VERSION 5.8 ;
BUSBITCHARS "[]" ;
DIVIDERCHAR "/" ;
UNITS
    DATABASE MICRONS 1000 ;
END UNITS

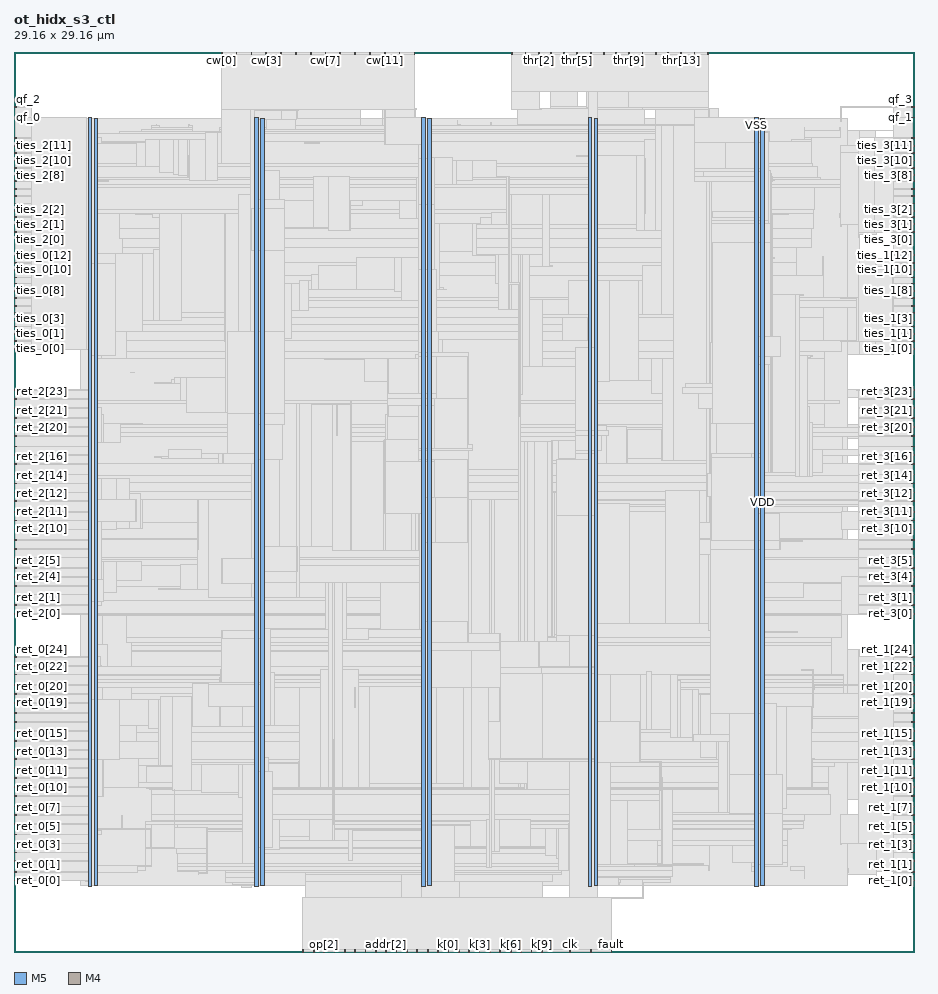
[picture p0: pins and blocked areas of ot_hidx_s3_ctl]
MACRO ot_hidx_s3_ctl
  FOREIGN ot_hidx_s3_ctl 0 0 ;
  CLASS BLOCK ;
  SIZE 29.16 BY 29.16 ;
  PIN addr[0]
    DIRECTION INPUT ;
    USE SIGNAL ;
    PORT
      LAYER M5 ;
        RECT  11.376 0 11.4 0.084 ;
    END
  END addr[0]
  PIN addr[1]
    DIRECTION INPUT ;
    USE SIGNAL ;
    PORT
      LAYER M5 ;
        RECT  11.712 0 11.736 0.084 ;
    END
  END addr[1]
  PIN addr[2]
    DIRECTION INPUT ;
    USE SIGNAL ;
    PORT
      LAYER M5 ;
        RECT  12.048 0 12.072 0.084 ;
    END
  END addr[2]
  PIN addr[3]
    DIRECTION INPUT ;
    USE SIGNAL ;
    PORT
      LAYER M5 ;
        RECT  12.384 0 12.408 0.084 ;
    END
  END addr[3]
  PIN addr[4]
    DIRECTION INPUT ;
    USE SIGNAL ;
    PORT
      LAYER M5 ;
        RECT  12.72 0 12.744 0.084 ;
    END
  END addr[4]
  PIN addr[5]
    DIRECTION INPUT ;
    USE SIGNAL ;
    PORT
      LAYER M5 ;
        RECT  13.056 0 13.08 0.084 ;
    END
  END addr[5]
  PIN addr[6]
    DIRECTION INPUT ;
    USE SIGNAL ;
    PORT
      LAYER M5 ;
        RECT  13.392 0 13.416 0.084 ;
    END
  END addr[6]
  PIN addr[7]
    DIRECTION INPUT ;
    USE SIGNAL ;
    PORT
      LAYER M5 ;
        RECT  13.728 0 13.752 0.084 ;
    END
  END addr[7]
  PIN clk
    DIRECTION INPUT ;
    USE SIGNAL ;
    PORT
      LAYER M5 ;
        RECT  18 0 18.024 0.084 ;
    END
  END clk
  PIN cw[0]
    DIRECTION OUTPUT ;
    USE SIGNAL ;
    PORT
      LAYER M5 ;
        RECT  6.72 29.076 6.744 29.16 ;
    END
  END cw[0]
  PIN cw[10]
    DIRECTION OUTPUT ;
    USE SIGNAL ;
    PORT
      LAYER M5 ;
        RECT  11.52 29.076 11.544 29.16 ;
    END
  END cw[10]
  PIN cw[11]
    DIRECTION OUTPUT ;
    USE SIGNAL ;
    PORT
      LAYER M5 ;
        RECT  12 29.076 12.024 29.16 ;
    END
  END cw[11]
  PIN cw[12]
    DIRECTION OUTPUT ;
    USE SIGNAL ;
    PORT
      LAYER M5 ;
        RECT  12.48 29.076 12.504 29.16 ;
    END
  END cw[12]
  PIN cw[13]
    DIRECTION OUTPUT ;
    USE SIGNAL ;
    PORT
      LAYER M5 ;
        RECT  12.96 29.076 12.984 29.16 ;
    END
  END cw[13]
  PIN cw[1]
    DIRECTION OUTPUT ;
    USE SIGNAL ;
    PORT
      LAYER M5 ;
        RECT  7.2 29.076 7.224 29.16 ;
    END
  END cw[1]
  PIN cw[2]
    DIRECTION OUTPUT ;
    USE SIGNAL ;
    PORT
      LAYER M5 ;
        RECT  7.68 29.076 7.704 29.16 ;
    END
  END cw[2]
  PIN cw[3]
    DIRECTION OUTPUT ;
    USE SIGNAL ;
    PORT
      LAYER M5 ;
        RECT  8.16 29.076 8.184 29.16 ;
    END
  END cw[3]
  PIN cw[4]
    DIRECTION OUTPUT ;
    USE SIGNAL ;
    PORT
      LAYER M5 ;
        RECT  8.64 29.076 8.664 29.16 ;
    END
  END cw[4]
  PIN cw[5]
    DIRECTION OUTPUT ;
    USE SIGNAL ;
    PORT
      LAYER M5 ;
        RECT  9.12 29.076 9.144 29.16 ;
    END
  END cw[5]
  PIN cw[6]
    DIRECTION OUTPUT ;
    USE SIGNAL ;
    PORT
      LAYER M5 ;
        RECT  9.6 29.076 9.624 29.16 ;
    END
  END cw[6]
  PIN cw[7]
    DIRECTION OUTPUT ;
    USE SIGNAL ;
    PORT
      LAYER M5 ;
        RECT  10.08 29.076 10.104 29.16 ;
    END
  END cw[7]
  PIN cw[8]
    DIRECTION OUTPUT ;
    USE SIGNAL ;
    PORT
      LAYER M5 ;
        RECT  10.56 29.076 10.584 29.16 ;
    END
  END cw[8]
  PIN cw[9]
    DIRECTION OUTPUT ;
    USE SIGNAL ;
    PORT
      LAYER M5 ;
        RECT  11.04 29.076 11.064 29.16 ;
    END
  END cw[9]
  PIN fault
    DIRECTION OUTPUT ;
    USE SIGNAL ;
    PORT
      LAYER M5 ;
        RECT  19.344 0 19.368 0.084 ;
    END
  END fault
  PIN k[0]
    DIRECTION INPUT ;
    USE SIGNAL ;
    PORT
      LAYER M5 ;
        RECT  14.064 0 14.088 0.084 ;
    END
  END k[0]
  PIN k[1]
    DIRECTION INPUT ;
    USE SIGNAL ;
    PORT
      LAYER M5 ;
        RECT  14.4 0 14.424 0.084 ;
    END
  END k[1]
  PIN k[2]
    DIRECTION INPUT ;
    USE SIGNAL ;
    PORT
      LAYER M5 ;
        RECT  14.736 0 14.76 0.084 ;
    END
  END k[2]
  PIN k[3]
    DIRECTION INPUT ;
    USE SIGNAL ;
    PORT
      LAYER M5 ;
        RECT  15.072 0 15.096 0.084 ;
    END
  END k[3]
  PIN k[4]
    DIRECTION INPUT ;
    USE SIGNAL ;
    PORT
      LAYER M5 ;
        RECT  15.408 0 15.432 0.084 ;
    END
  END k[4]
  PIN k[5]
    DIRECTION INPUT ;
    USE SIGNAL ;
    PORT
      LAYER M5 ;
        RECT  15.744 0 15.768 0.084 ;
    END
  END k[5]
  PIN k[6]
    DIRECTION INPUT ;
    USE SIGNAL ;
    PORT
      LAYER M5 ;
        RECT  16.08 0 16.104 0.084 ;
    END
  END k[6]
  PIN k[7]
    DIRECTION INPUT ;
    USE SIGNAL ;
    PORT
      LAYER M5 ;
        RECT  16.416 0 16.44 0.084 ;
    END
  END k[7]
  PIN k[8]
    DIRECTION INPUT ;
    USE SIGNAL ;
    PORT
      LAYER M5 ;
        RECT  16.752 0 16.776 0.084 ;
    END
  END k[8]
  PIN k[9]
    DIRECTION INPUT ;
    USE SIGNAL ;
    PORT
      LAYER M5 ;
        RECT  17.088 0 17.112 0.084 ;
    END
  END k[9]
  PIN op[0]
    DIRECTION INPUT ;
    USE SIGNAL ;
    PORT
      LAYER M5 ;
        RECT  9.36 0 9.384 0.084 ;
    END
  END op[0]
  PIN op[1]
    DIRECTION INPUT ;
    USE SIGNAL ;
    PORT
      LAYER M5 ;
        RECT  9.696 0 9.72 0.084 ;
    END
  END op[1]
  PIN op[2]
    DIRECTION INPUT ;
    USE SIGNAL ;
    PORT
      LAYER M5 ;
        RECT  10.032 0 10.056 0.084 ;
    END
  END op[2]
  PIN op[3]
    DIRECTION INPUT ;
    USE SIGNAL ;
    PORT
      LAYER M5 ;
        RECT  10.368 0 10.392 0.084 ;
    END
  END op[3]
  PIN pass[0]
    DIRECTION INPUT ;
    USE SIGNAL ;
    PORT
      LAYER M5 ;
        RECT  10.704 0 10.728 0.084 ;
    END
  END pass[0]
  PIN pass[1]
    DIRECTION INPUT ;
    USE SIGNAL ;
    PORT
      LAYER M5 ;
        RECT  11.04 0 11.064 0.084 ;
    END
  END pass[1]
  PIN qf_0
    DIRECTION INPUT ;
    USE SIGNAL ;
    PORT
      LAYER M4 ;
        RECT  0 27.024 0.084 27.048 ;
    END
  END qf_0
  PIN qf_1
    DIRECTION INPUT ;
    USE SIGNAL ;
    PORT
      LAYER M4 ;
        RECT  29.076 27.024 29.16 27.048 ;
    END
  END qf_1
  PIN qf_2
    DIRECTION INPUT ;
    USE SIGNAL ;
    PORT
      LAYER M4 ;
        RECT  0 27.36 0.084 27.384 ;
    END
  END qf_2
  PIN qf_3
    DIRECTION INPUT ;
    USE SIGNAL ;
    PORT
      LAYER M4 ;
        RECT  29.076 27.36 29.16 27.384 ;
    END
  END qf_3
  PIN ret_0[0]
    DIRECTION INPUT ;
    USE SIGNAL ;
    PORT
      LAYER M4 ;
        RECT  0 2.304 0.084 2.328 ;
    END
  END ret_0[0]
  PIN ret_0[10]
    DIRECTION INPUT ;
    USE SIGNAL ;
    PORT
      LAYER M4 ;
        RECT  0 5.328 0.084 5.352 ;
    END
  END ret_0[10]
  PIN ret_0[11]
    DIRECTION INPUT ;
    USE SIGNAL ;
    PORT
      LAYER M4 ;
        RECT  0 5.616 0.084 5.64 ;
    END
  END ret_0[11]
  PIN ret_0[12]
    DIRECTION INPUT ;
    USE SIGNAL ;
    PORT
      LAYER M4 ;
        RECT  0 5.952 0.084 5.976 ;
    END
  END ret_0[12]
  PIN ret_0[13]
    DIRECTION INPUT ;
    USE SIGNAL ;
    PORT
      LAYER M4 ;
        RECT  0 6.24 0.084 6.264 ;
    END
  END ret_0[13]
  PIN ret_0[14]
    DIRECTION INPUT ;
    USE SIGNAL ;
    PORT
      LAYER M4 ;
        RECT  0 6.528 0.084 6.552 ;
    END
  END ret_0[14]
  PIN ret_0[15]
    DIRECTION INPUT ;
    USE SIGNAL ;
    PORT
      LAYER M4 ;
        RECT  0 6.816 0.084 6.84 ;
    END
  END ret_0[15]
  PIN ret_0[16]
    DIRECTION INPUT ;
    USE SIGNAL ;
    PORT
      LAYER M4 ;
        RECT  0 7.152 0.084 7.176 ;
    END
  END ret_0[16]
  PIN ret_0[17]
    DIRECTION INPUT ;
    USE SIGNAL ;
    PORT
      LAYER M4 ;
        RECT  0 7.44 0.084 7.464 ;
    END
  END ret_0[17]
  PIN ret_0[18]
    DIRECTION INPUT ;
    USE SIGNAL ;
    PORT
      LAYER M4 ;
        RECT  0 7.728 0.084 7.752 ;
    END
  END ret_0[18]
  PIN ret_0[19]
    DIRECTION INPUT ;
    USE SIGNAL ;
    PORT
      LAYER M4 ;
        RECT  0 8.064 0.084 8.088 ;
    END
  END ret_0[19]
  PIN ret_0[1]
    DIRECTION INPUT ;
    USE SIGNAL ;
    PORT
      LAYER M4 ;
        RECT  0 2.592 0.084 2.616 ;
    END
  END ret_0[1]
  PIN ret_0[20]
    DIRECTION INPUT ;
    USE SIGNAL ;
    PORT
      LAYER M4 ;
        RECT  0 8.352 0.084 8.376 ;
    END
  END ret_0[20]
  PIN ret_0[21]
    DIRECTION INPUT ;
    USE SIGNAL ;
    PORT
      LAYER M4 ;
        RECT  0 8.64 0.084 8.664 ;
    END
  END ret_0[21]
  PIN ret_0[22]
    DIRECTION INPUT ;
    USE SIGNAL ;
    PORT
      LAYER M4 ;
        RECT  0 8.976 0.084 9 ;
    END
  END ret_0[22]
  PIN ret_0[23]
    DIRECTION INPUT ;
    USE SIGNAL ;
    PORT
      LAYER M4 ;
        RECT  0 9.264 0.084 9.288 ;
    END
  END ret_0[23]
  PIN ret_0[24]
    DIRECTION INPUT ;
    USE SIGNAL ;
    PORT
      LAYER M4 ;
        RECT  0 9.552 0.084 9.576 ;
    END
  END ret_0[24]
  PIN ret_0[2]
    DIRECTION INPUT ;
    USE SIGNAL ;
    PORT
      LAYER M4 ;
        RECT  0 2.928 0.084 2.952 ;
    END
  END ret_0[2]
  PIN ret_0[3]
    DIRECTION INPUT ;
    USE SIGNAL ;
    PORT
      LAYER M4 ;
        RECT  0 3.216 0.084 3.24 ;
    END
  END ret_0[3]
  PIN ret_0[4]
    DIRECTION INPUT ;
    USE SIGNAL ;
    PORT
      LAYER M4 ;
        RECT  0 3.504 0.084 3.528 ;
    END
  END ret_0[4]
  PIN ret_0[5]
    DIRECTION INPUT ;
    USE SIGNAL ;
    PORT
      LAYER M4 ;
        RECT  0 3.792 0.084 3.816 ;
    END
  END ret_0[5]
  PIN ret_0[6]
    DIRECTION INPUT ;
    USE SIGNAL ;
    PORT
      LAYER M4 ;
        RECT  0 4.128 0.084 4.152 ;
    END
  END ret_0[6]
  PIN ret_0[7]
    DIRECTION INPUT ;
    USE SIGNAL ;
    PORT
      LAYER M4 ;
        RECT  0 4.416 0.084 4.44 ;
    END
  END ret_0[7]
  PIN ret_0[8]
    DIRECTION INPUT ;
    USE SIGNAL ;
    PORT
      LAYER M4 ;
        RECT  0 4.704 0.084 4.728 ;
    END
  END ret_0[8]
  PIN ret_0[9]
    DIRECTION INPUT ;
    USE SIGNAL ;
    PORT
      LAYER M4 ;
        RECT  0 5.04 0.084 5.064 ;
    END
  END ret_0[9]
  PIN ret_1[0]
    DIRECTION INPUT ;
    USE SIGNAL ;
    PORT
      LAYER M4 ;
        RECT  29.076 2.304 29.16 2.328 ;
    END
  END ret_1[0]
  PIN ret_1[10]
    DIRECTION INPUT ;
    USE SIGNAL ;
    PORT
      LAYER M4 ;
        RECT  29.076 5.328 29.16 5.352 ;
    END
  END ret_1[10]
  PIN ret_1[11]
    DIRECTION INPUT ;
    USE SIGNAL ;
    PORT
      LAYER M4 ;
        RECT  29.076 5.616 29.16 5.64 ;
    END
  END ret_1[11]
  PIN ret_1[12]
    DIRECTION INPUT ;
    USE SIGNAL ;
    PORT
      LAYER M4 ;
        RECT  29.076 5.952 29.16 5.976 ;
    END
  END ret_1[12]
  PIN ret_1[13]
    DIRECTION INPUT ;
    USE SIGNAL ;
    PORT
      LAYER M4 ;
        RECT  29.076 6.24 29.16 6.264 ;
    END
  END ret_1[13]
  PIN ret_1[14]
    DIRECTION INPUT ;
    USE SIGNAL ;
    PORT
      LAYER M4 ;
        RECT  29.076 6.528 29.16 6.552 ;
    END
  END ret_1[14]
  PIN ret_1[15]
    DIRECTION INPUT ;
    USE SIGNAL ;
    PORT
      LAYER M4 ;
        RECT  29.076 6.816 29.16 6.84 ;
    END
  END ret_1[15]
  PIN ret_1[16]
    DIRECTION INPUT ;
    USE SIGNAL ;
    PORT
      LAYER M4 ;
        RECT  29.076 7.152 29.16 7.176 ;
    END
  END ret_1[16]
  PIN ret_1[17]
    DIRECTION INPUT ;
    USE SIGNAL ;
    PORT
      LAYER M4 ;
        RECT  29.076 7.44 29.16 7.464 ;
    END
  END ret_1[17]
  PIN ret_1[18]
    DIRECTION INPUT ;
    USE SIGNAL ;
    PORT
      LAYER M4 ;
        RECT  29.076 7.728 29.16 7.752 ;
    END
  END ret_1[18]
  PIN ret_1[19]
    DIRECTION INPUT ;
    USE SIGNAL ;
    PORT
      LAYER M4 ;
        RECT  29.076 8.064 29.16 8.088 ;
    END
  END ret_1[19]
  PIN ret_1[1]
    DIRECTION INPUT ;
    USE SIGNAL ;
    PORT
      LAYER M4 ;
        RECT  29.076 2.592 29.16 2.616 ;
    END
  END ret_1[1]
  PIN ret_1[20]
    DIRECTION INPUT ;
    USE SIGNAL ;
    PORT
      LAYER M4 ;
        RECT  29.076 8.352 29.16 8.376 ;
    END
  END ret_1[20]
  PIN ret_1[21]
    DIRECTION INPUT ;
    USE SIGNAL ;
    PORT
      LAYER M4 ;
        RECT  29.076 8.64 29.16 8.664 ;
    END
  END ret_1[21]
  PIN ret_1[22]
    DIRECTION INPUT ;
    USE SIGNAL ;
    PORT
      LAYER M4 ;
        RECT  29.076 8.976 29.16 9 ;
    END
  END ret_1[22]
  PIN ret_1[23]
    DIRECTION INPUT ;
    USE SIGNAL ;
    PORT
      LAYER M4 ;
        RECT  29.076 9.264 29.16 9.288 ;
    END
  END ret_1[23]
  PIN ret_1[24]
    DIRECTION INPUT ;
    USE SIGNAL ;
    PORT
      LAYER M4 ;
        RECT  29.076 9.552 29.16 9.576 ;
    END
  END ret_1[24]
  PIN ret_1[2]
    DIRECTION INPUT ;
    USE SIGNAL ;
    PORT
      LAYER M4 ;
        RECT  29.076 2.928 29.16 2.952 ;
    END
  END ret_1[2]
  PIN ret_1[3]
    DIRECTION INPUT ;
    USE SIGNAL ;
    PORT
      LAYER M4 ;
        RECT  29.076 3.216 29.16 3.24 ;
    END
  END ret_1[3]
  PIN ret_1[4]
    DIRECTION INPUT ;
    USE SIGNAL ;
    PORT
      LAYER M4 ;
        RECT  29.076 3.504 29.16 3.528 ;
    END
  END ret_1[4]
  PIN ret_1[5]
    DIRECTION INPUT ;
    USE SIGNAL ;
    PORT
      LAYER M4 ;
        RECT  29.076 3.792 29.16 3.816 ;
    END
  END ret_1[5]
  PIN ret_1[6]
    DIRECTION INPUT ;
    USE SIGNAL ;
    PORT
      LAYER M4 ;
        RECT  29.076 4.128 29.16 4.152 ;
    END
  END ret_1[6]
  PIN ret_1[7]
    DIRECTION INPUT ;
    USE SIGNAL ;
    PORT
      LAYER M4 ;
        RECT  29.076 4.416 29.16 4.44 ;
    END
  END ret_1[7]
  PIN ret_1[8]
    DIRECTION INPUT ;
    USE SIGNAL ;
    PORT
      LAYER M4 ;
        RECT  29.076 4.704 29.16 4.728 ;
    END
  END ret_1[8]
  PIN ret_1[9]
    DIRECTION INPUT ;
    USE SIGNAL ;
    PORT
      LAYER M4 ;
        RECT  29.076 5.04 29.16 5.064 ;
    END
  END ret_1[9]
  PIN ret_2[0]
    DIRECTION INPUT ;
    USE SIGNAL ;
    PORT
      LAYER M4 ;
        RECT  0 10.944 0.084 10.968 ;
    END
  END ret_2[0]
  PIN ret_2[10]
    DIRECTION INPUT ;
    USE SIGNAL ;
    PORT
      LAYER M4 ;
        RECT  0 13.968 0.084 13.992 ;
    END
  END ret_2[10]
  PIN ret_2[11]
    DIRECTION INPUT ;
    USE SIGNAL ;
    PORT
      LAYER M4 ;
        RECT  0 14.256 0.084 14.28 ;
    END
  END ret_2[11]
  PIN ret_2[12]
    DIRECTION INPUT ;
    USE SIGNAL ;
    PORT
      LAYER M4 ;
        RECT  0 14.592 0.084 14.616 ;
    END
  END ret_2[12]
  PIN ret_2[13]
    DIRECTION INPUT ;
    USE SIGNAL ;
    PORT
      LAYER M4 ;
        RECT  0 14.88 0.084 14.904 ;
    END
  END ret_2[13]
  PIN ret_2[14]
    DIRECTION INPUT ;
    USE SIGNAL ;
    PORT
      LAYER M4 ;
        RECT  0 15.168 0.084 15.192 ;
    END
  END ret_2[14]
  PIN ret_2[15]
    DIRECTION INPUT ;
    USE SIGNAL ;
    PORT
      LAYER M4 ;
        RECT  0 15.456 0.084 15.48 ;
    END
  END ret_2[15]
  PIN ret_2[16]
    DIRECTION INPUT ;
    USE SIGNAL ;
    PORT
      LAYER M4 ;
        RECT  0 15.792 0.084 15.816 ;
    END
  END ret_2[16]
  PIN ret_2[17]
    DIRECTION INPUT ;
    USE SIGNAL ;
    PORT
      LAYER M4 ;
        RECT  0 16.08 0.084 16.104 ;
    END
  END ret_2[17]
  PIN ret_2[18]
    DIRECTION INPUT ;
    USE SIGNAL ;
    PORT
      LAYER M4 ;
        RECT  0 16.368 0.084 16.392 ;
    END
  END ret_2[18]
  PIN ret_2[19]
    DIRECTION INPUT ;
    USE SIGNAL ;
    PORT
      LAYER M4 ;
        RECT  0 16.704 0.084 16.728 ;
    END
  END ret_2[19]
  PIN ret_2[1]
    DIRECTION INPUT ;
    USE SIGNAL ;
    PORT
      LAYER M4 ;
        RECT  0 11.232 0.084 11.256 ;
    END
  END ret_2[1]
  PIN ret_2[20]
    DIRECTION INPUT ;
    USE SIGNAL ;
    PORT
      LAYER M4 ;
        RECT  0 16.992 0.084 17.016 ;
    END
  END ret_2[20]
  PIN ret_2[21]
    DIRECTION INPUT ;
    USE SIGNAL ;
    PORT
      LAYER M4 ;
        RECT  0 17.28 0.084 17.304 ;
    END
  END ret_2[21]
  PIN ret_2[22]
    DIRECTION INPUT ;
    USE SIGNAL ;
    PORT
      LAYER M4 ;
        RECT  0 17.616 0.084 17.64 ;
    END
  END ret_2[22]
  PIN ret_2[23]
    DIRECTION INPUT ;
    USE SIGNAL ;
    PORT
      LAYER M4 ;
        RECT  0 17.904 0.084 17.928 ;
    END
  END ret_2[23]
  PIN ret_2[24]
    DIRECTION INPUT ;
    USE SIGNAL ;
    PORT
      LAYER M4 ;
        RECT  0 18.192 0.084 18.216 ;
    END
  END ret_2[24]
  PIN ret_2[2]
    DIRECTION INPUT ;
    USE SIGNAL ;
    PORT
      LAYER M4 ;
        RECT  0 11.568 0.084 11.592 ;
    END
  END ret_2[2]
  PIN ret_2[3]
    DIRECTION INPUT ;
    USE SIGNAL ;
    PORT
      LAYER M4 ;
        RECT  0 11.856 0.084 11.88 ;
    END
  END ret_2[3]
  PIN ret_2[4]
    DIRECTION INPUT ;
    USE SIGNAL ;
    PORT
      LAYER M4 ;
        RECT  0 12.144 0.084 12.168 ;
    END
  END ret_2[4]
  PIN ret_2[5]
    DIRECTION INPUT ;
    USE SIGNAL ;
    PORT
      LAYER M4 ;
        RECT  0 12.432 0.084 12.456 ;
    END
  END ret_2[5]
  PIN ret_2[6]
    DIRECTION INPUT ;
    USE SIGNAL ;
    PORT
      LAYER M4 ;
        RECT  0 12.768 0.084 12.792 ;
    END
  END ret_2[6]
  PIN ret_2[7]
    DIRECTION INPUT ;
    USE SIGNAL ;
    PORT
      LAYER M4 ;
        RECT  0 13.056 0.084 13.08 ;
    END
  END ret_2[7]
  PIN ret_2[8]
    DIRECTION INPUT ;
    USE SIGNAL ;
    PORT
      LAYER M4 ;
        RECT  0 13.344 0.084 13.368 ;
    END
  END ret_2[8]
  PIN ret_2[9]
    DIRECTION INPUT ;
    USE SIGNAL ;
    PORT
      LAYER M4 ;
        RECT  0 13.68 0.084 13.704 ;
    END
  END ret_2[9]
  PIN ret_3[0]
    DIRECTION INPUT ;
    USE SIGNAL ;
    PORT
      LAYER M4 ;
        RECT  29.076 10.944 29.16 10.968 ;
    END
  END ret_3[0]
  PIN ret_3[10]
    DIRECTION INPUT ;
    USE SIGNAL ;
    PORT
      LAYER M4 ;
        RECT  29.076 13.968 29.16 13.992 ;
    END
  END ret_3[10]
  PIN ret_3[11]
    DIRECTION INPUT ;
    USE SIGNAL ;
    PORT
      LAYER M4 ;
        RECT  29.076 14.256 29.16 14.28 ;
    END
  END ret_3[11]
  PIN ret_3[12]
    DIRECTION INPUT ;
    USE SIGNAL ;
    PORT
      LAYER M4 ;
        RECT  29.076 14.592 29.16 14.616 ;
    END
  END ret_3[12]
  PIN ret_3[13]
    DIRECTION INPUT ;
    USE SIGNAL ;
    PORT
      LAYER M4 ;
        RECT  29.076 14.88 29.16 14.904 ;
    END
  END ret_3[13]
  PIN ret_3[14]
    DIRECTION INPUT ;
    USE SIGNAL ;
    PORT
      LAYER M4 ;
        RECT  29.076 15.168 29.16 15.192 ;
    END
  END ret_3[14]
  PIN ret_3[15]
    DIRECTION INPUT ;
    USE SIGNAL ;
    PORT
      LAYER M4 ;
        RECT  29.076 15.456 29.16 15.48 ;
    END
  END ret_3[15]
  PIN ret_3[16]
    DIRECTION INPUT ;
    USE SIGNAL ;
    PORT
      LAYER M4 ;
        RECT  29.076 15.792 29.16 15.816 ;
    END
  END ret_3[16]
  PIN ret_3[17]
    DIRECTION INPUT ;
    USE SIGNAL ;
    PORT
      LAYER M4 ;
        RECT  29.076 16.08 29.16 16.104 ;
    END
  END ret_3[17]
  PIN ret_3[18]
    DIRECTION INPUT ;
    USE SIGNAL ;
    PORT
      LAYER M4 ;
        RECT  29.076 16.368 29.16 16.392 ;
    END
  END ret_3[18]
  PIN ret_3[19]
    DIRECTION INPUT ;
    USE SIGNAL ;
    PORT
      LAYER M4 ;
        RECT  29.076 16.704 29.16 16.728 ;
    END
  END ret_3[19]
  PIN ret_3[1]
    DIRECTION INPUT ;
    USE SIGNAL ;
    PORT
      LAYER M4 ;
        RECT  29.076 11.232 29.16 11.256 ;
    END
  END ret_3[1]
  PIN ret_3[20]
    DIRECTION INPUT ;
    USE SIGNAL ;
    PORT
      LAYER M4 ;
        RECT  29.076 16.992 29.16 17.016 ;
    END
  END ret_3[20]
  PIN ret_3[21]
    DIRECTION INPUT ;
    USE SIGNAL ;
    PORT
      LAYER M4 ;
        RECT  29.076 17.28 29.16 17.304 ;
    END
  END ret_3[21]
  PIN ret_3[22]
    DIRECTION INPUT ;
    USE SIGNAL ;
    PORT
      LAYER M4 ;
        RECT  29.076 17.616 29.16 17.64 ;
    END
  END ret_3[22]
  PIN ret_3[23]
    DIRECTION INPUT ;
    USE SIGNAL ;
    PORT
      LAYER M4 ;
        RECT  29.076 17.904 29.16 17.928 ;
    END
  END ret_3[23]
  PIN ret_3[24]
    DIRECTION INPUT ;
    USE SIGNAL ;
    PORT
      LAYER M4 ;
        RECT  29.076 18.192 29.16 18.216 ;
    END
  END ret_3[24]
  PIN ret_3[2]
    DIRECTION INPUT ;
    USE SIGNAL ;
    PORT
      LAYER M4 ;
        RECT  29.076 11.568 29.16 11.592 ;
    END
  END ret_3[2]
  PIN ret_3[3]
    DIRECTION INPUT ;
    USE SIGNAL ;
    PORT
      LAYER M4 ;
        RECT  29.076 11.856 29.16 11.88 ;
    END
  END ret_3[3]
  PIN ret_3[4]
    DIRECTION INPUT ;
    USE SIGNAL ;
    PORT
      LAYER M4 ;
        RECT  29.076 12.144 29.16 12.168 ;
    END
  END ret_3[4]
  PIN ret_3[5]
    DIRECTION INPUT ;
    USE SIGNAL ;
    PORT
      LAYER M4 ;
        RECT  29.076 12.432 29.16 12.456 ;
    END
  END ret_3[5]
  PIN ret_3[6]
    DIRECTION INPUT ;
    USE SIGNAL ;
    PORT
      LAYER M4 ;
        RECT  29.076 12.768 29.16 12.792 ;
    END
  END ret_3[6]
  PIN ret_3[7]
    DIRECTION INPUT ;
    USE SIGNAL ;
    PORT
      LAYER M4 ;
        RECT  29.076 13.056 29.16 13.08 ;
    END
  END ret_3[7]
  PIN ret_3[8]
    DIRECTION INPUT ;
    USE SIGNAL ;
    PORT
      LAYER M4 ;
        RECT  29.076 13.344 29.16 13.368 ;
    END
  END ret_3[8]
  PIN ret_3[9]
    DIRECTION INPUT ;
    USE SIGNAL ;
    PORT
      LAYER M4 ;
        RECT  29.076 13.68 29.16 13.704 ;
    END
  END ret_3[9]
  PIN rst_n
    DIRECTION INPUT ;
    USE SIGNAL ;
    PORT
      LAYER M5 ;
        RECT  18.672 0 18.696 0.084 ;
    END
  END rst_n
  PIN thr[0]
    DIRECTION OUTPUT ;
    USE SIGNAL ;
    PORT
      LAYER M5 ;
        RECT  16.128 29.076 16.152 29.16 ;
    END
  END thr[0]
  PIN thr[10]
    DIRECTION OUTPUT ;
    USE SIGNAL ;
    PORT
      LAYER M5 ;
        RECT  20.352 29.076 20.376 29.16 ;
    END
  END thr[10]
  PIN thr[11]
    DIRECTION OUTPUT ;
    USE SIGNAL ;
    PORT
      LAYER M5 ;
        RECT  20.784 29.076 20.808 29.16 ;
    END
  END thr[11]
  PIN thr[12]
    DIRECTION OUTPUT ;
    USE SIGNAL ;
    PORT
      LAYER M5 ;
        RECT  21.168 29.076 21.192 29.16 ;
    END
  END thr[12]
  PIN thr[13]
    DIRECTION OUTPUT ;
    USE SIGNAL ;
    PORT
      LAYER M5 ;
        RECT  21.6 29.076 21.624 29.16 ;
    END
  END thr[13]
  PIN thr[14]
    DIRECTION OUTPUT ;
    USE SIGNAL ;
    PORT
      LAYER M5 ;
        RECT  22.032 29.076 22.056 29.16 ;
    END
  END thr[14]
  PIN thr[15]
    DIRECTION OUTPUT ;
    USE SIGNAL ;
    PORT
      LAYER M5 ;
        RECT  22.464 29.076 22.488 29.16 ;
    END
  END thr[15]
  PIN thr[1]
    DIRECTION OUTPUT ;
    USE SIGNAL ;
    PORT
      LAYER M5 ;
        RECT  16.56 29.076 16.584 29.16 ;
    END
  END thr[1]
  PIN thr[2]
    DIRECTION OUTPUT ;
    USE SIGNAL ;
    PORT
      LAYER M5 ;
        RECT  16.992 29.076 17.016 29.16 ;
    END
  END thr[2]
  PIN thr[3]
    DIRECTION OUTPUT ;
    USE SIGNAL ;
    PORT
      LAYER M5 ;
        RECT  17.376 29.076 17.4 29.16 ;
    END
  END thr[3]
  PIN thr[4]
    DIRECTION OUTPUT ;
    USE SIGNAL ;
    PORT
      LAYER M5 ;
        RECT  17.808 29.076 17.832 29.16 ;
    END
  END thr[4]
  PIN thr[5]
    DIRECTION OUTPUT ;
    USE SIGNAL ;
    PORT
      LAYER M5 ;
        RECT  18.24 29.076 18.264 29.16 ;
    END
  END thr[5]
  PIN thr[6]
    DIRECTION OUTPUT ;
    USE SIGNAL ;
    PORT
      LAYER M5 ;
        RECT  18.672 29.076 18.696 29.16 ;
    END
  END thr[6]
  PIN thr[7]
    DIRECTION OUTPUT ;
    USE SIGNAL ;
    PORT
      LAYER M5 ;
        RECT  19.104 29.076 19.128 29.16 ;
    END
  END thr[7]
  PIN thr[8]
    DIRECTION OUTPUT ;
    USE SIGNAL ;
    PORT
      LAYER M5 ;
        RECT  19.488 29.076 19.512 29.16 ;
    END
  END thr[8]
  PIN thr[9]
    DIRECTION OUTPUT ;
    USE SIGNAL ;
    PORT
      LAYER M5 ;
        RECT  19.92 29.076 19.944 29.16 ;
    END
  END thr[9]
  PIN ties_0[0]
    DIRECTION OUTPUT ;
    USE SIGNAL ;
    PORT
      LAYER M4 ;
        RECT  0 19.536 0.084 19.56 ;
    END
  END ties_0[0]
  PIN ties_0[10]
    DIRECTION OUTPUT ;
    USE SIGNAL ;
    PORT
      LAYER M4 ;
        RECT  0 21.84 0.084 21.864 ;
    END
  END ties_0[10]
  PIN ties_0[11]
    DIRECTION OUTPUT ;
    USE SIGNAL ;
    PORT
      LAYER M4 ;
        RECT  0 22.08 0.084 22.104 ;
    END
  END ties_0[11]
  PIN ties_0[12]
    DIRECTION OUTPUT ;
    USE SIGNAL ;
    PORT
      LAYER M4 ;
        RECT  0 22.32 0.084 22.344 ;
    END
  END ties_0[12]
  PIN ties_0[13]
    DIRECTION OUTPUT ;
    USE SIGNAL ;
    PORT
      LAYER M4 ;
        RECT  0 22.56 0.084 22.584 ;
    END
  END ties_0[13]
  PIN ties_0[1]
    DIRECTION OUTPUT ;
    USE SIGNAL ;
    PORT
      LAYER M4 ;
        RECT  0 19.776 0.084 19.8 ;
    END
  END ties_0[1]
  PIN ties_0[2]
    DIRECTION OUTPUT ;
    USE SIGNAL ;
    PORT
      LAYER M4 ;
        RECT  0 20.016 0.084 20.04 ;
    END
  END ties_0[2]
  PIN ties_0[3]
    DIRECTION OUTPUT ;
    USE SIGNAL ;
    PORT
      LAYER M4 ;
        RECT  0 20.256 0.084 20.28 ;
    END
  END ties_0[3]
  PIN ties_0[4]
    DIRECTION OUTPUT ;
    USE SIGNAL ;
    PORT
      LAYER M4 ;
        RECT  0 20.448 0.084 20.472 ;
    END
  END ties_0[4]
  PIN ties_0[5]
    DIRECTION OUTPUT ;
    USE SIGNAL ;
    PORT
      LAYER M4 ;
        RECT  0 20.688 0.084 20.712 ;
    END
  END ties_0[5]
  PIN ties_0[6]
    DIRECTION OUTPUT ;
    USE SIGNAL ;
    PORT
      LAYER M4 ;
        RECT  0 20.928 0.084 20.952 ;
    END
  END ties_0[6]
  PIN ties_0[7]
    DIRECTION OUTPUT ;
    USE SIGNAL ;
    PORT
      LAYER M4 ;
        RECT  0 21.168 0.084 21.192 ;
    END
  END ties_0[7]
  PIN ties_0[8]
    DIRECTION OUTPUT ;
    USE SIGNAL ;
    PORT
      LAYER M4 ;
        RECT  0 21.408 0.084 21.432 ;
    END
  END ties_0[8]
  PIN ties_0[9]
    DIRECTION OUTPUT ;
    USE SIGNAL ;
    PORT
      LAYER M4 ;
        RECT  0 21.648 0.084 21.672 ;
    END
  END ties_0[9]
  PIN ties_1[0]
    DIRECTION OUTPUT ;
    USE SIGNAL ;
    PORT
      LAYER M4 ;
        RECT  29.076 19.536 29.16 19.56 ;
    END
  END ties_1[0]
  PIN ties_1[10]
    DIRECTION OUTPUT ;
    USE SIGNAL ;
    PORT
      LAYER M4 ;
        RECT  29.076 21.84 29.16 21.864 ;
    END
  END ties_1[10]
  PIN ties_1[11]
    DIRECTION OUTPUT ;
    USE SIGNAL ;
    PORT
      LAYER M4 ;
        RECT  29.076 22.08 29.16 22.104 ;
    END
  END ties_1[11]
  PIN ties_1[12]
    DIRECTION OUTPUT ;
    USE SIGNAL ;
    PORT
      LAYER M4 ;
        RECT  29.076 22.32 29.16 22.344 ;
    END
  END ties_1[12]
  PIN ties_1[13]
    DIRECTION OUTPUT ;
    USE SIGNAL ;
    PORT
      LAYER M4 ;
        RECT  29.076 22.56 29.16 22.584 ;
    END
  END ties_1[13]
  PIN ties_1[1]
    DIRECTION OUTPUT ;
    USE SIGNAL ;
    PORT
      LAYER M4 ;
        RECT  29.076 19.776 29.16 19.8 ;
    END
  END ties_1[1]
  PIN ties_1[2]
    DIRECTION OUTPUT ;
    USE SIGNAL ;
    PORT
      LAYER M4 ;
        RECT  29.076 20.016 29.16 20.04 ;
    END
  END ties_1[2]
  PIN ties_1[3]
    DIRECTION OUTPUT ;
    USE SIGNAL ;
    PORT
      LAYER M4 ;
        RECT  29.076 20.256 29.16 20.28 ;
    END
  END ties_1[3]
  PIN ties_1[4]
    DIRECTION OUTPUT ;
    USE SIGNAL ;
    PORT
      LAYER M4 ;
        RECT  29.076 20.448 29.16 20.472 ;
    END
  END ties_1[4]
  PIN ties_1[5]
    DIRECTION OUTPUT ;
    USE SIGNAL ;
    PORT
      LAYER M4 ;
        RECT  29.076 20.688 29.16 20.712 ;
    END
  END ties_1[5]
  PIN ties_1[6]
    DIRECTION OUTPUT ;
    USE SIGNAL ;
    PORT
      LAYER M4 ;
        RECT  29.076 20.928 29.16 20.952 ;
    END
  END ties_1[6]
  PIN ties_1[7]
    DIRECTION OUTPUT ;
    USE SIGNAL ;
    PORT
      LAYER M4 ;
        RECT  29.076 21.168 29.16 21.192 ;
    END
  END ties_1[7]
  PIN ties_1[8]
    DIRECTION OUTPUT ;
    USE SIGNAL ;
    PORT
      LAYER M4 ;
        RECT  29.076 21.408 29.16 21.432 ;
    END
  END ties_1[8]
  PIN ties_1[9]
    DIRECTION OUTPUT ;
    USE SIGNAL ;
    PORT
      LAYER M4 ;
        RECT  29.076 21.648 29.16 21.672 ;
    END
  END ties_1[9]
  PIN ties_2[0]
    DIRECTION OUTPUT ;
    USE SIGNAL ;
    PORT
      LAYER M4 ;
        RECT  0 23.328 0.084 23.352 ;
    END
  END ties_2[0]
  PIN ties_2[10]
    DIRECTION OUTPUT ;
    USE SIGNAL ;
    PORT
      LAYER M4 ;
        RECT  0 25.632 0.084 25.656 ;
    END
  END ties_2[10]
  PIN ties_2[11]
    DIRECTION OUTPUT ;
    USE SIGNAL ;
    PORT
      LAYER M4 ;
        RECT  0 25.872 0.084 25.896 ;
    END
  END ties_2[11]
  PIN ties_2[12]
    DIRECTION OUTPUT ;
    USE SIGNAL ;
    PORT
      LAYER M4 ;
        RECT  0 26.112 0.084 26.136 ;
    END
  END ties_2[12]
  PIN ties_2[13]
    DIRECTION OUTPUT ;
    USE SIGNAL ;
    PORT
      LAYER M4 ;
        RECT  0 26.352 0.084 26.376 ;
    END
  END ties_2[13]
  PIN ties_2[1]
    DIRECTION OUTPUT ;
    USE SIGNAL ;
    PORT
      LAYER M4 ;
        RECT  0 23.568 0.084 23.592 ;
    END
  END ties_2[1]
  PIN ties_2[2]
    DIRECTION OUTPUT ;
    USE SIGNAL ;
    PORT
      LAYER M4 ;
        RECT  0 23.808 0.084 23.832 ;
    END
  END ties_2[2]
  PIN ties_2[3]
    DIRECTION OUTPUT ;
    USE SIGNAL ;
    PORT
      LAYER M4 ;
        RECT  0 24 0.084 24.024 ;
    END
  END ties_2[3]
  PIN ties_2[4]
    DIRECTION OUTPUT ;
    USE SIGNAL ;
    PORT
      LAYER M4 ;
        RECT  0 24.24 0.084 24.264 ;
    END
  END ties_2[4]
  PIN ties_2[5]
    DIRECTION OUTPUT ;
    USE SIGNAL ;
    PORT
      LAYER M4 ;
        RECT  0 24.48 0.084 24.504 ;
    END
  END ties_2[5]
  PIN ties_2[6]
    DIRECTION OUTPUT ;
    USE SIGNAL ;
    PORT
      LAYER M4 ;
        RECT  0 24.72 0.084 24.744 ;
    END
  END ties_2[6]
  PIN ties_2[7]
    DIRECTION OUTPUT ;
    USE SIGNAL ;
    PORT
      LAYER M4 ;
        RECT  0 24.96 0.084 24.984 ;
    END
  END ties_2[7]
  PIN ties_2[8]
    DIRECTION OUTPUT ;
    USE SIGNAL ;
    PORT
      LAYER M4 ;
        RECT  0 25.152 0.084 25.176 ;
    END
  END ties_2[8]
  PIN ties_2[9]
    DIRECTION OUTPUT ;
    USE SIGNAL ;
    PORT
      LAYER M4 ;
        RECT  0 25.392 0.084 25.416 ;
    END
  END ties_2[9]
  PIN ties_3[0]
    DIRECTION OUTPUT ;
    USE SIGNAL ;
    PORT
      LAYER M4 ;
        RECT  29.076 23.328 29.16 23.352 ;
    END
  END ties_3[0]
  PIN ties_3[10]
    DIRECTION OUTPUT ;
    USE SIGNAL ;
    PORT
      LAYER M4 ;
        RECT  29.076 25.632 29.16 25.656 ;
    END
  END ties_3[10]
  PIN ties_3[11]
    DIRECTION OUTPUT ;
    USE SIGNAL ;
    PORT
      LAYER M4 ;
        RECT  29.076 25.872 29.16 25.896 ;
    END
  END ties_3[11]
  PIN ties_3[12]
    DIRECTION OUTPUT ;
    USE SIGNAL ;
    PORT
      LAYER M4 ;
        RECT  29.076 26.112 29.16 26.136 ;
    END
  END ties_3[12]
  PIN ties_3[13]
    DIRECTION OUTPUT ;
    USE SIGNAL ;
    PORT
      LAYER M4 ;
        RECT  29.076 26.352 29.16 26.376 ;
    END
  END ties_3[13]
  PIN ties_3[1]
    DIRECTION OUTPUT ;
    USE SIGNAL ;
    PORT
      LAYER M4 ;
        RECT  29.076 23.568 29.16 23.592 ;
    END
  END ties_3[1]
  PIN ties_3[2]
    DIRECTION OUTPUT ;
    USE SIGNAL ;
    PORT
      LAYER M4 ;
        RECT  29.076 23.808 29.16 23.832 ;
    END
  END ties_3[2]
  PIN ties_3[3]
    DIRECTION OUTPUT ;
    USE SIGNAL ;
    PORT
      LAYER M4 ;
        RECT  29.076 24 29.16 24.024 ;
    END
  END ties_3[3]
  PIN ties_3[4]
    DIRECTION OUTPUT ;
    USE SIGNAL ;
    PORT
      LAYER M4 ;
        RECT  29.076 24.24 29.16 24.264 ;
    END
  END ties_3[4]
  PIN ties_3[5]
    DIRECTION OUTPUT ;
    USE SIGNAL ;
    PORT
      LAYER M4 ;
        RECT  29.076 24.48 29.16 24.504 ;
    END
  END ties_3[5]
  PIN ties_3[6]
    DIRECTION OUTPUT ;
    USE SIGNAL ;
    PORT
      LAYER M4 ;
        RECT  29.076 24.72 29.16 24.744 ;
    END
  END ties_3[6]
  PIN ties_3[7]
    DIRECTION OUTPUT ;
    USE SIGNAL ;
    PORT
      LAYER M4 ;
        RECT  29.076 24.96 29.16 24.984 ;
    END
  END ties_3[7]
  PIN ties_3[8]
    DIRECTION OUTPUT ;
    USE SIGNAL ;
    PORT
      LAYER M4 ;
        RECT  29.076 25.152 29.16 25.176 ;
    END
  END ties_3[8]
  PIN ties_3[9]
    DIRECTION OUTPUT ;
    USE SIGNAL ;
    PORT
      LAYER M4 ;
        RECT  29.076 25.392 29.16 25.416 ;
    END
  END ties_3[9]
  PIN VDD
    DIRECTION INOUT ;
    USE POWER ;
    PORT
      LAYER M5 ;
        RECT  24.192 2.151 24.312 27.009 ;
        RECT  18.792 2.151 18.912 27.009 ;
        RECT  13.392 2.151 13.512 27.009 ;
        RECT  7.992 2.151 8.112 27.009 ;
        RECT  2.592 2.151 2.712 27.009 ;
    END
  END VDD
  PIN VSS
    DIRECTION INOUT ;
    USE GROUND ;
    PORT
      LAYER M5 ;
        RECT  24 2.137 24.12 27.023 ;
        RECT  18.6 2.137 18.72 27.023 ;
        RECT  13.2 2.137 13.32 27.023 ;
        RECT  7.8 2.137 7.92 27.023 ;
        RECT  2.4 2.137 2.52 27.023 ;
    END
  END VSS
  # OT_OBS_CLOSED layer=M5 d_um=1.536 added=51
  OBS
    LAYER RVTN ;
     RECT  2.16 2.16 27 2.295 ;
     RECT  2.16 2.565 27 2.835 ;
     RECT  2.16 3.105 27 3.375 ;
     RECT  2.16 3.645 27 3.915 ;
     RECT  2.16 4.185 27 4.455 ;
     RECT  2.16 4.725 27 4.995 ;
     RECT  2.16 5.265 27 5.535 ;
     RECT  2.16 5.805 27 6.075 ;
     RECT  2.16 6.345 27 6.615 ;
     RECT  2.16 6.885 27 7.155 ;
     RECT  2.16 7.425 27 7.695 ;
     RECT  2.16 7.965 27 8.235 ;
     RECT  2.16 8.505 27 8.775 ;
     RECT  2.16 9.045 27 9.315 ;
     RECT  2.16 9.585 27 9.855 ;
     RECT  2.16 10.125 27 10.395 ;
     RECT  2.16 10.665 27 10.935 ;
     RECT  2.16 11.205 27 11.475 ;
     RECT  2.16 11.745 27 12.015 ;
     RECT  2.16 12.285 27 12.555 ;
     RECT  2.16 12.825 27 13.095 ;
     RECT  2.16 13.365 27 13.635 ;
     RECT  2.16 13.905 27 14.175 ;
     RECT  2.16 14.445 27 14.715 ;
     RECT  2.16 14.985 27 15.255 ;
     RECT  2.16 15.525 27 15.795 ;
     RECT  2.16 16.065 27 16.335 ;
     RECT  2.16 16.605 27 16.875 ;
     RECT  2.16 17.145 27 17.415 ;
     RECT  2.16 17.685 27 17.955 ;
     RECT  2.16 18.225 27 18.495 ;
     RECT  2.16 18.765 27 19.035 ;
     RECT  2.16 19.305 27 19.575 ;
     RECT  2.16 19.845 27 20.115 ;
     RECT  2.16 20.385 27 20.655 ;
     RECT  2.16 20.925 27 21.195 ;
     RECT  2.16 21.465 27 21.735 ;
     RECT  2.16 22.005 27 22.275 ;
     RECT  2.16 22.545 27 22.815 ;
     RECT  2.16 23.085 27 23.355 ;
     RECT  2.16 23.625 27 23.895 ;
     RECT  2.16 24.165 27 24.435 ;
     RECT  2.16 24.705 27 24.975 ;
     RECT  2.16 25.245 27 25.515 ;
     RECT  2.16 25.785 27 26.055 ;
     RECT  2.16 26.325 27 26.595 ;
     RECT  2.16 26.865 27 27 ;
    LAYER RVTP ;
     RECT  2.16 2.295 27 2.565 ;
     RECT  2.16 2.835 27 3.105 ;
     RECT  2.16 3.375 27 3.645 ;
     RECT  2.16 3.915 27 4.185 ;
     RECT  2.16 4.455 27 4.725 ;
     RECT  2.16 4.995 27 5.265 ;
     RECT  2.16 5.535 27 5.805 ;
     RECT  2.16 6.075 27 6.345 ;
     RECT  2.16 6.615 27 6.885 ;
     RECT  2.16 7.155 27 7.425 ;
     RECT  2.16 7.695 27 7.965 ;
     RECT  2.16 8.235 27 8.505 ;
     RECT  2.16 8.775 27 9.045 ;
     RECT  2.16 9.315 27 9.585 ;
     RECT  2.16 9.855 27 10.125 ;
     RECT  2.16 10.395 27 10.665 ;
     RECT  2.16 10.935 27 11.205 ;
     RECT  2.16 11.475 27 11.745 ;
     RECT  2.16 12.015 27 12.285 ;
     RECT  2.16 12.555 27 12.825 ;
     RECT  2.16 13.095 27 13.365 ;
     RECT  2.16 13.635 27 13.905 ;
     RECT  2.16 14.175 27 14.445 ;
     RECT  2.16 14.715 27 14.985 ;
     RECT  2.16 15.255 27 15.525 ;
     RECT  2.16 15.795 27 16.065 ;
     RECT  2.16 16.335 27 16.605 ;
     RECT  2.16 16.875 27 17.145 ;
     RECT  2.16 17.415 27 17.685 ;
     RECT  2.16 17.955 27 18.225 ;
     RECT  2.16 18.495 27 18.765 ;
     RECT  2.16 19.035 27 19.305 ;
     RECT  2.16 19.575 27 19.845 ;
     RECT  2.16 20.115 27 20.385 ;
     RECT  2.16 20.655 27 20.925 ;
     RECT  2.16 21.195 27 21.465 ;
     RECT  2.16 21.735 27 22.005 ;
     RECT  2.16 22.275 27 22.545 ;
     RECT  2.16 22.815 27 23.085 ;
     RECT  2.16 23.355 27 23.625 ;
     RECT  2.16 23.895 27 24.165 ;
     RECT  2.16 24.435 27 24.705 ;
     RECT  2.16 24.975 27 25.245 ;
     RECT  2.16 25.515 27 25.785 ;
     RECT  2.16 26.055 27 26.325 ;
     RECT  2.16 26.595 27 26.865 ;
    LAYER M1 ;
     RECT  2.16 2.151 27 27.009 ;
    LAYER M2 ;
     RECT  0.103 23.166 1.147 23.886 ;
     RECT  1.147 22.986 1.175 23.886 ;
     RECT  0.103 3.042 2.16 3.06 ;
     RECT  0.535 4.5 2.16 4.518 ;
     RECT  0.103 14.724 2.16 14.742 ;
     RECT  0.103 17.658 2.16 17.676 ;
     RECT  0.535 20.826 2.16 20.844 ;
     RECT  0.535 21.636 2.16 22.032 ;
     RECT  1.175 22.986 2.16 23.004 ;
     RECT  1.175 23.868 2.16 23.886 ;
     RECT  0.535 26.766 2.16 26.784 ;
     RECT  2.16 2.151 7.375 27.009 ;
     RECT  7.375 2.106 7.691 27.009 ;
     RECT  7.691 2.151 27 27.009 ;
     RECT  27 17.964 27.347 18.216 ;
     RECT  27 4.932 27.383 9.81 ;
     RECT  27 10.98 27.383 11.736 ;
     RECT  27 12.528 27.383 13.086 ;
     RECT  27 14.454 27.383 15.822 ;
     RECT  27 16.65 27.383 17.1 ;
     RECT  27 19.35 27.383 26.622 ;
     RECT  27.383 6.012 27.419 6.03 ;
     RECT  27.383 6.822 27.419 7.11 ;
     RECT  27.383 14.922 27.419 14.94 ;
     RECT  27.383 12.798 27.455 12.816 ;
     RECT  27.347 17.964 27.887 18.018 ;
     RECT  27.419 7.092 27.923 7.11 ;
     RECT  27.383 19.35 27.923 22.464 ;
     RECT  27.383 26.406 27.923 26.622 ;
     RECT  27 2.502 27.959 3.87 ;
     RECT  27.383 8.01 27.959 9.414 ;
     RECT  27.923 21.636 27.959 22.464 ;
     RECT  27.383 23.256 27.959 23.814 ;
     RECT  27.383 24.876 27.959 24.894 ;
     RECT  27.923 19.35 28.499 19.944 ;
     RECT  27.959 2.61 28.535 3.87 ;
     RECT  27.959 8.01 28.535 9.036 ;
     RECT  27.383 16.65 28.535 16.668 ;
     RECT  27.887 17.964 28.535 17.982 ;
     RECT  27.959 22.212 28.535 22.464 ;
     RECT  27.959 23.796 28.535 23.814 ;
     RECT  27.923 26.604 28.535 26.622 ;
     RECT  28.535 8.28 28.571 8.298 ;
     RECT  28.535 22.212 29.075 22.23 ;
    LAYER M3 ;
     RECT  12.348 0.091 12.366 0.139 ;
     RECT  10.8 0.091 10.818 1.723 ;
     RECT  12.348 0.139 12.798 1.723 ;
     RECT  7.38 2.101 7.686 2.143 ;
     RECT  18.576 1.723 18.594 2.143 ;
     RECT  7.38 2.143 7.905 2.191 ;
     RECT  7.092 2.191 7.905 2.263 ;
     RECT  19.584 2.191 19.602 2.263 ;
     RECT  20.376 1.723 20.394 2.263 ;
     RECT  2.415 2.143 2.505 2.299 ;
     RECT  9.432 1.723 17.118 2.299 ;
     RECT  19.584 2.263 19.638 2.335 ;
     RECT  20.376 2.263 21.258 2.335 ;
     RECT  2.304 2.299 2.505 2.413 ;
     RECT  6.84 2.263 7.905 2.413 ;
     RECT  18.576 2.143 18.705 2.413 ;
     RECT  19.584 2.335 21.258 2.413 ;
     RECT  24.015 2.143 24.105 2.413 ;
     RECT  18.576 2.413 21.258 2.461 ;
     RECT  9.432 2.299 17.442 2.497 ;
     RECT  27.936 2.299 27.954 2.525 ;
     RECT  6.84 2.413 8.097 2.569 ;
     RECT  9.432 2.497 17.73 2.569 ;
     RECT  5.976 2.497 5.994 2.605 ;
     RECT  24.015 2.413 24.297 2.605 ;
     RECT  3.96 2.587 3.978 2.641 ;
     RECT  5.292 2.605 5.994 2.641 ;
     RECT  6.84 2.569 17.73 2.641 ;
     RECT  18.576 2.461 21.33 2.641 ;
     RECT  25.596 2.371 25.614 2.641 ;
     RECT  27.036 2.569 27.054 2.714 ;
     RECT  3.78 2.641 4.266 2.759 ;
     RECT  5.292 2.641 21.33 2.759 ;
     RECT  25.164 2.641 25.614 2.759 ;
     RECT  2.304 2.413 2.697 2.767 ;
     RECT  3.96 2.759 4.266 2.767 ;
     RECT  23.904 2.605 24.297 2.767 ;
     RECT  3.96 2.767 4.446 2.795 ;
     RECT  20.844 2.759 21.33 2.803 ;
     RECT  22.5 2.641 22.518 2.803 ;
     RECT  2.304 2.767 2.934 2.813 ;
     RECT  5.292 2.759 20.106 2.861 ;
     RECT  23.904 2.767 25.074 2.911 ;
     RECT  0.108 2.923 0.126 3.065 ;
     RECT  5.292 2.861 19.854 3.181 ;
     RECT  4.248 2.795 4.446 3.343 ;
     RECT  5.256 3.181 19.854 3.343 ;
     RECT  4.248 3.343 19.854 3.389 ;
     RECT  20.844 2.803 22.518 3.451 ;
     RECT  23.292 2.911 25.074 3.451 ;
     RECT  5.292 3.389 19.854 3.613 ;
     RECT  20.844 3.451 25.074 3.613 ;
     RECT  2.304 2.813 2.697 3.811 ;
     RECT  28.512 2.587 28.53 3.875 ;
     RECT  2.304 3.811 2.826 3.947 ;
     RECT  5.292 3.613 25.074 3.955 ;
     RECT  5.292 3.955 25.182 3.991 ;
     RECT  4.248 3.389 4.446 4.117 ;
     RECT  5.292 3.991 25.578 4.117 ;
     RECT  4.248 4.117 25.578 4.217 ;
     RECT  4.464 4.217 25.578 4.261 ;
     RECT  3.492 3.979 3.51 4.415 ;
     RECT  26.784 3.499 26.802 4.451 ;
     RECT  4.464 4.261 25.614 4.459 ;
     RECT  0.54 4.495 0.558 4.733 ;
     RECT  2.304 3.947 2.697 5.035 ;
     RECT  4.464 4.459 26.442 5.099 ;
     RECT  4.464 5.099 26.406 5.269 ;
     RECT  4.392 5.269 26.406 5.305 ;
     RECT  4.284 5.305 26.406 5.323 ;
     RECT  2.304 5.035 2.898 5.369 ;
     RECT  3.996 5.323 26.406 5.495 ;
     RECT  27.36 4.699 27.378 5.947 ;
     RECT  4.284 5.495 26.406 6.007 ;
     RECT  2.415 5.369 2.898 6.043 ;
     RECT  0.108 5.947 0.126 6.077 ;
     RECT  4.284 6.007 26.586 6.151 ;
     RECT  27.36 5.947 27.414 6.151 ;
     RECT  2.415 6.043 3.33 6.235 ;
     RECT  4.284 6.151 27.414 6.235 ;
     RECT  2.304 6.235 27.414 6.809 ;
     RECT  3.96 6.809 27.414 6.811 ;
     RECT  3.96 6.811 27.918 7.115 ;
     RECT  2.304 6.809 3.222 7.579 ;
     RECT  3.96 7.115 27.378 7.579 ;
     RECT  2.304 7.579 27.378 7.619 ;
     RECT  28.512 7.723 28.53 8.033 ;
     RECT  28.548 8.059 28.566 8.303 ;
     RECT  3.816 7.619 27.378 8.381 ;
     RECT  2.304 7.619 2.862 8.581 ;
     RECT  3.816 8.381 26.874 8.581 ;
     RECT  2.304 8.581 26.874 8.735 ;
     RECT  2.34 8.735 26.874 8.843 ;
     RECT  2.34 8.843 16.83 8.969 ;
     RECT  17.784 8.843 26.874 8.969 ;
     RECT  2.34 8.969 16.614 9.005 ;
     RECT  17.892 8.969 26.874 9.005 ;
     RECT  28.512 8.971 28.53 9.041 ;
     RECT  2.415 9.005 16.614 9.239 ;
     RECT  27.936 9.259 27.954 9.419 ;
     RECT  3.816 9.239 16.614 9.751 ;
     RECT  3.816 9.751 16.83 9.781 ;
     RECT  27.36 9.547 27.378 9.815 ;
     RECT  3.816 9.781 17.118 9.931 ;
     RECT  17.892 9.005 26.478 9.931 ;
     RECT  2.415 9.239 3.042 9.959 ;
     RECT  3.816 9.931 26.478 10.021 ;
     RECT  3.636 10.021 26.478 10.201 ;
     RECT  2.415 9.959 2.862 10.903 ;
     RECT  3.636 10.201 26.802 10.903 ;
     RECT  2.415 10.903 26.802 10.939 ;
     RECT  2.412 10.939 26.838 10.975 ;
     RECT  2.412 10.975 27.378 11.399 ;
     RECT  2.412 11.399 17.658 11.851 ;
     RECT  18.504 11.399 27.378 11.939 ;
     RECT  2.304 11.851 17.658 12.515 ;
     RECT  2.412 12.515 17.658 12.523 ;
     RECT  2.412 12.523 17.802 12.721 ;
     RECT  18.615 11.939 27.378 12.721 ;
     RECT  2.412 12.721 27.378 12.793 ;
     RECT  2.412 12.793 27.45 13.373 ;
     RECT  2.412 13.373 26.838 13.405 ;
     RECT  2.376 13.405 26.838 14.251 ;
     RECT  2.304 14.251 26.838 14.449 ;
     RECT  2.304 14.449 27.378 14.485 ;
     RECT  2.268 14.485 27.378 14.621 ;
     RECT  2.304 14.621 27.378 14.675 ;
     RECT  2.376 14.675 27.378 14.917 ;
     RECT  2.376 14.917 27.414 15.197 ;
     RECT  0.108 13.963 0.126 15.293 ;
     RECT  2.376 15.197 27.378 15.448 ;
     RECT  2.304 15.448 27.378 15.827 ;
     RECT  28.512 16.363 28.53 16.673 ;
     RECT  2.304 15.827 26.838 16.699 ;
     RECT  2.304 16.699 27.378 16.835 ;
     RECT  2.34 16.835 27.378 16.979 ;
     RECT  2.34 16.979 26.262 17.105 ;
     RECT  27.36 16.979 27.378 17.309 ;
     RECT  2.415 17.105 26.262 17.761 ;
     RECT  2.415 17.761 26.73 17.879 ;
     RECT  28.512 17.611 28.53 17.899 ;
     RECT  0.108 17.275 0.126 17.933 ;
     RECT  27.864 17.899 28.53 17.987 ;
     RECT  27.864 17.987 27.882 18.023 ;
     RECT  27.324 18.184 27.342 18.221 ;
     RECT  2.415 17.879 26.262 19.229 ;
     RECT  3.636 19.229 26.262 19.471 ;
     RECT  3.636 19.471 26.802 19.805 ;
     RECT  2.415 19.229 2.826 20.011 ;
     RECT  28.476 19.345 28.494 20.045 ;
     RECT  2.304 20.011 2.826 20.107 ;
     RECT  3.636 19.805 17.766 20.107 ;
     RECT  2.304 20.107 17.766 20.345 ;
     RECT  3.636 20.345 17.766 20.551 ;
     RECT  18.576 19.805 26.226 20.551 ;
     RECT  27.9 20.191 27.918 20.683 ;
     RECT  3.636 20.551 26.226 20.893 ;
     RECT  27.324 20.683 27.918 20.893 ;
     RECT  2.304 20.345 2.697 21.115 ;
     RECT  3.636 20.893 27.918 21.115 ;
     RECT  2.304 21.115 27.918 21.197 ;
     RECT  27.36 21.197 27.918 21.631 ;
     RECT  27.36 21.631 27.954 21.869 ;
     RECT  2.304 21.197 26.226 21.929 ;
     RECT  27.36 21.869 27.378 22.115 ;
     RECT  2.304 21.929 25.362 22.343 ;
     RECT  0.54 20.821 0.558 22.349 ;
     RECT  29.052 22.207 29.07 22.349 ;
     RECT  26.208 21.929 26.226 22.541 ;
     RECT  28.512 22.441 28.53 22.589 ;
     RECT  3.528 22.343 25.362 22.819 ;
     RECT  3.528 22.819 25.83 23.125 ;
     RECT  1.152 22.981 1.17 23.189 ;
     RECT  27.36 23.161 27.378 23.251 ;
     RECT  27.36 23.251 27.954 23.357 ;
     RECT  3.42 23.125 25.83 23.431 ;
     RECT  26.784 23.521 26.802 23.791 ;
     RECT  27.936 23.357 27.954 23.791 ;
     RECT  27.936 23.791 28.53 23.837 ;
     RECT  26.748 23.791 26.802 23.927 ;
     RECT  2.304 22.343 2.697 23.935 ;
     RECT  3.42 23.431 25.902 23.935 ;
     RECT  0.108 23.161 0.126 24.029 ;
     RECT  28.512 23.837 28.53 24.029 ;
     RECT  2.304 23.935 25.902 24.061 ;
     RECT  26.784 23.927 26.802 24.235 ;
     RECT  2.304 24.061 25.938 24.781 ;
     RECT  26.784 24.235 27.378 24.781 ;
     RECT  2.304 24.781 27.378 24.871 ;
     RECT  2.304 24.871 27.954 25.043 ;
     RECT  2.304 25.043 26.118 25.079 ;
     RECT  27.36 25.043 27.954 25.181 ;
     RECT  2.304 25.079 26.046 25.439 ;
     RECT  2.304 25.439 25.866 25.547 ;
     RECT  27.36 25.181 27.378 25.861 ;
     RECT  26.784 25.861 27.378 26.141 ;
     RECT  2.304 25.547 25.83 26.249 ;
     RECT  25.2 26.249 25.83 26.321 ;
     RECT  25.596 26.321 25.83 26.401 ;
     RECT  27.9 26.347 27.918 26.429 ;
     RECT  2.304 26.249 24.462 26.519 ;
     RECT  3.42 26.519 24.462 26.573 ;
     RECT  3.42 26.573 24.354 26.591 ;
     RECT  25.596 26.401 26.766 26.627 ;
     RECT  4.14 26.591 5.778 26.663 ;
     RECT  6.66 26.591 24.354 26.663 ;
     RECT  4.464 26.663 5.778 26.699 ;
     RECT  6.66 26.663 8.19 26.699 ;
     RECT  25.596 26.627 25.614 26.699 ;
     RECT  26.748 26.627 26.766 26.699 ;
     RECT  2.304 26.519 2.697 26.747 ;
     RECT  4.464 26.699 4.698 26.789 ;
     RECT  5.652 26.699 5.778 26.789 ;
     RECT  9.108 26.663 22.986 26.789 ;
     RECT  23.832 26.663 24.354 26.789 ;
     RECT  4.608 26.789 4.626 26.825 ;
     RECT  5.652 26.789 5.67 26.825 ;
     RECT  14.364 26.789 14.454 26.825 ;
     RECT  16.308 26.789 22.986 26.825 ;
     RECT  15.444 26.789 15.462 26.861 ;
     RECT  21.636 26.825 22.806 26.861 ;
     RECT  14.364 26.825 14.382 26.933 ;
     RECT  24.015 26.789 24.354 26.933 ;
     RECT  9.108 26.789 11.214 27.005 ;
     RECT  2.304 26.747 2.505 27.017 ;
     RECT  11.952 26.789 13.305 27.017 ;
     RECT  24.015 26.933 24.105 27.017 ;
     RECT  2.304 27.017 2.322 27.053 ;
     RECT  28.512 26.599 28.53 27.053 ;
     RECT  9.18 27.005 11.214 27.293 ;
     RECT  6.768 26.699 8.19 27.341 ;
     RECT  9.648 27.293 11.214 27.341 ;
     RECT  11.952 27.017 13.014 27.341 ;
     RECT  16.308 26.825 20.43 27.341 ;
     RECT  21.636 26.861 21.654 27.341 ;
     RECT  22.788 26.861 22.806 27.341 ;
     RECT  0.54 26.761 0.558 27.389 ;
     RECT  17.388 27.341 19.926 27.389 ;
     RECT  26.784 26.905 26.802 27.389 ;
     RECT  17.388 27.389 18.27 27.917 ;
     RECT  19.116 27.389 19.35 27.917 ;
     RECT  19.332 27.917 19.35 27.965 ;
    LAYER M4 ;
     RECT  0.084 19.536 0.569 19.56 ;
     RECT  0.06 19.56 0.569 19.776 ;
     RECT  0.084 19.776 0.569 19.8 ;
     RECT  0.06 19.8 0.569 20.016 ;
     RECT  0.084 20.016 0.569 20.04 ;
     RECT  0.06 20.04 0.569 20.256 ;
     RECT  0.084 20.256 0.569 20.28 ;
     RECT  0.06 20.28 0.569 20.448 ;
     RECT  0.084 20.448 0.569 20.472 ;
     RECT  0.06 20.472 0.569 20.688 ;
     RECT  0.084 20.688 0.569 20.712 ;
     RECT  0.06 20.712 0.569 20.928 ;
     RECT  0.084 20.928 0.569 20.952 ;
     RECT  0.06 20.952 0.569 21.168 ;
     RECT  0.084 21.168 0.569 21.192 ;
     RECT  0.06 21.192 0.569 21.408 ;
     RECT  0.084 21.408 0.569 21.432 ;
     RECT  0.06 21.432 0.569 21.648 ;
     RECT  0.084 21.648 0.569 21.672 ;
     RECT  0.06 21.672 0.569 21.84 ;
     RECT  0.084 21.84 0.569 21.864 ;
     RECT  0.06 21.864 0.569 22.08 ;
     RECT  0.084 22.08 0.569 22.104 ;
     RECT  0.06 22.104 0.569 22.32 ;
     RECT  0.084 22.32 0.569 22.344 ;
     RECT  0.06 22.344 0.569 22.56 ;
     RECT  0.084 22.56 0.569 22.584 ;
     RECT  0.06 22.584 0.569 23.328 ;
     RECT  0.084 23.328 0.569 23.352 ;
     RECT  0.06 23.352 0.569 23.568 ;
     RECT  0.084 23.568 0.569 23.592 ;
     RECT  0.06 23.592 0.569 23.808 ;
     RECT  0.084 23.808 0.569 23.832 ;
     RECT  0.06 23.832 0.569 24 ;
     RECT  0.084 24 0.569 24.024 ;
     RECT  0.06 24.024 0.569 24.24 ;
     RECT  0.084 24.24 0.569 24.264 ;
     RECT  0.06 24.264 0.569 24.48 ;
     RECT  0.084 24.48 0.569 24.504 ;
     RECT  0.06 24.504 0.569 24.72 ;
     RECT  0.084 24.72 0.569 24.744 ;
     RECT  0.06 24.744 0.569 24.96 ;
     RECT  0.084 24.96 0.569 24.984 ;
     RECT  0.06 24.984 0.569 25.152 ;
     RECT  0.084 25.152 0.569 25.176 ;
     RECT  0.06 25.176 0.569 25.392 ;
     RECT  0.084 25.392 0.569 25.416 ;
     RECT  0.06 25.416 0.569 25.632 ;
     RECT  0.084 25.632 0.569 25.656 ;
     RECT  0.06 25.656 0.569 25.872 ;
     RECT  0.084 25.872 0.569 25.896 ;
     RECT  0.06 25.896 0.569 26.112 ;
     RECT  0.084 26.112 0.569 26.136 ;
     RECT  0.06 26.136 0.569 26.352 ;
     RECT  0.084 26.352 0.569 26.376 ;
     RECT  0.06 26.376 0.569 27.024 ;
     RECT  0.084 27.024 0.569 27.048 ;
     RECT  0.06 27.048 0.569 27.36 ;
     RECT  0.084 27.36 0.569 27.384 ;
     RECT  0.569 19.536 2.333 27.048 ;
     RECT  0.084 2.304 2.408 2.328 ;
     RECT  0.06 2.328 2.408 2.592 ;
     RECT  0.084 2.592 2.408 2.616 ;
     RECT  0.06 2.616 2.408 2.928 ;
     RECT  0.084 2.928 2.408 2.952 ;
     RECT  0.06 2.952 2.408 3.216 ;
     RECT  0.084 3.216 2.408 3.24 ;
     RECT  0.06 3.24 2.408 3.504 ;
     RECT  0.084 3.504 2.408 3.528 ;
     RECT  0.06 3.528 2.408 3.792 ;
     RECT  0.084 3.792 2.408 3.816 ;
     RECT  0.06 3.816 2.408 4.128 ;
     RECT  0.084 4.128 2.408 4.152 ;
     RECT  0.06 4.152 2.408 4.416 ;
     RECT  0.084 4.416 2.408 4.44 ;
     RECT  0.06 4.44 2.408 4.704 ;
     RECT  0.084 4.704 2.408 4.728 ;
     RECT  0.06 4.728 2.408 5.04 ;
     RECT  0.084 5.04 2.408 5.064 ;
     RECT  0.06 5.064 2.408 5.328 ;
     RECT  0.084 5.328 2.408 5.352 ;
     RECT  0.06 5.352 2.408 5.616 ;
     RECT  0.084 5.616 2.408 5.64 ;
     RECT  0.06 5.64 2.408 5.952 ;
     RECT  0.084 5.952 2.408 5.976 ;
     RECT  0.06 5.976 2.408 6.24 ;
     RECT  0.084 6.24 2.408 6.264 ;
     RECT  0.06 6.264 2.408 6.528 ;
     RECT  0.084 6.528 2.408 6.552 ;
     RECT  0.06 6.552 2.408 6.816 ;
     RECT  0.084 6.816 2.408 6.84 ;
     RECT  0.06 6.84 2.408 7.152 ;
     RECT  0.084 7.152 2.408 7.176 ;
     RECT  0.06 7.176 2.408 7.44 ;
     RECT  0.084 7.44 2.408 7.464 ;
     RECT  0.06 7.464 2.408 7.728 ;
     RECT  0.084 7.728 2.408 7.752 ;
     RECT  0.06 7.752 2.408 8.064 ;
     RECT  0.084 8.064 2.408 8.088 ;
     RECT  0.06 8.088 2.408 8.352 ;
     RECT  0.084 8.352 2.408 8.376 ;
     RECT  0.06 8.376 2.408 8.64 ;
     RECT  0.084 8.64 2.408 8.664 ;
     RECT  0.06 8.664 2.408 8.976 ;
     RECT  0.084 8.976 2.408 9 ;
     RECT  0.06 9 2.408 9.264 ;
     RECT  0.084 9.264 2.408 9.288 ;
     RECT  0.06 9.288 2.408 9.552 ;
     RECT  0.084 9.552 2.408 9.576 ;
     RECT  0.084 10.944 2.408 10.968 ;
     RECT  0.06 10.968 2.408 11.232 ;
     RECT  0.084 11.232 2.408 11.256 ;
     RECT  0.06 11.256 2.408 11.568 ;
     RECT  0.084 11.568 2.408 11.592 ;
     RECT  0.06 11.592 2.408 11.856 ;
     RECT  0.084 11.856 2.408 11.88 ;
     RECT  0.06 11.88 2.408 12.144 ;
     RECT  0.084 12.144 2.408 12.168 ;
     RECT  0.06 12.168 2.408 12.432 ;
     RECT  0.084 12.432 2.408 12.456 ;
     RECT  0.06 12.456 2.408 12.768 ;
     RECT  0.084 12.768 2.408 12.792 ;
     RECT  0.06 12.792 2.408 13.056 ;
     RECT  0.084 13.056 2.408 13.08 ;
     RECT  0.06 13.08 2.408 13.344 ;
     RECT  0.084 13.344 2.408 13.368 ;
     RECT  0.06 13.368 2.408 13.68 ;
     RECT  0.084 13.68 2.408 13.704 ;
     RECT  0.06 13.704 2.408 13.968 ;
     RECT  0.084 13.968 2.408 13.992 ;
     RECT  0.06 13.992 2.408 14.256 ;
     RECT  0.084 14.256 2.408 14.28 ;
     RECT  0.06 14.28 2.408 14.592 ;
     RECT  0.084 14.592 2.408 14.616 ;
     RECT  0.06 14.616 2.408 14.88 ;
     RECT  0.084 14.88 2.408 14.904 ;
     RECT  0.06 14.904 2.408 15.168 ;
     RECT  0.084 15.168 2.408 15.192 ;
     RECT  0.06 15.192 2.408 15.456 ;
     RECT  0.084 15.456 2.408 15.48 ;
     RECT  0.06 15.48 2.408 15.792 ;
     RECT  0.084 15.792 2.408 15.816 ;
     RECT  0.06 15.816 2.408 16.08 ;
     RECT  0.084 16.08 2.408 16.104 ;
     RECT  0.06 16.104 2.408 16.368 ;
     RECT  0.084 16.368 2.408 16.392 ;
     RECT  0.06 16.392 2.408 16.704 ;
     RECT  0.084 16.704 2.408 16.728 ;
     RECT  0.06 16.728 2.408 16.992 ;
     RECT  0.084 16.992 2.408 17.016 ;
     RECT  0.06 17.016 2.408 17.28 ;
     RECT  0.084 17.28 2.408 17.304 ;
     RECT  0.06 17.304 2.408 17.616 ;
     RECT  0.084 17.616 2.408 17.64 ;
     RECT  0.06 17.64 2.408 17.904 ;
     RECT  0.084 17.904 2.408 17.928 ;
     RECT  0.06 17.928 2.408 18.192 ;
     RECT  0.084 18.192 2.408 18.216 ;
     RECT  2.333 19.536 2.408 27.012 ;
     RECT  2.408 2.148 2.512 27.012 ;
     RECT  2.512 2.418 2.704 26.742 ;
     RECT  2.704 9.264 2.801 9.576 ;
     RECT  2.801 9.264 2.837 9.288 ;
     RECT  2.704 11.232 2.837 15.336 ;
     RECT  2.704 16.512 2.837 17.64 ;
     RECT  2.704 26.208 2.837 26.376 ;
     RECT  2.704 5.04 2.873 8.184 ;
     RECT  2.873 5.04 2.909 6.264 ;
     RECT  2.837 16.512 2.909 17.4 ;
     RECT  2.837 11.376 2.915 12.648 ;
     RECT  2.704 24.96 3.053 24.984 ;
     RECT  2.704 19.344 3.299 22.632 ;
     RECT  2.915 11.664 3.305 12.648 ;
     RECT  2.837 13.68 3.305 15.336 ;
     RECT  2.909 16.512 3.449 17.112 ;
     RECT  3.305 13.728 3.737 15.336 ;
     RECT  3.769 18.768 3.917 18.792 ;
     RECT  2.837 26.208 3.985 26.232 ;
     RECT  2.704 2.592 3.989 2.808 ;
     RECT  2.909 5.328 4.025 6.264 ;
     RECT  3.737 13.728 4.097 14.856 ;
     RECT  3.305 12.048 4.133 12.648 ;
     RECT  4.097 13.728 4.169 14.664 ;
     RECT  3.449 17.088 4.169 17.112 ;
     RECT  3.299 20.112 4.169 22.632 ;
     RECT  3.985 25.44 4.273 26.232 ;
     RECT  2.873 7.344 4.345 8.184 ;
     RECT  3.989 2.784 4.385 2.808 ;
     RECT  2.704 3.984 4.417 4.008 ;
     RECT  4.417 3.36 4.457 4.008 ;
     RECT  3.949 23.904 4.489 23.928 ;
     RECT  4.169 20.448 4.525 22.632 ;
     RECT  4.025 6.048 4.669 6.264 ;
     RECT  4.345 7.248 4.669 8.184 ;
     RECT  4.525 20.448 4.705 22.776 ;
     RECT  4.489 23.808 4.705 23.928 ;
     RECT  4.273 25.44 4.705 26.328 ;
     RECT  4.669 6.048 4.741 8.184 ;
     RECT  4.561 16.032 4.777 16.056 ;
     RECT  4.777 15.984 4.993 16.056 ;
     RECT  4.561 18.432 5.101 18.456 ;
     RECT  4.741 6.048 5.132 8.28 ;
     RECT  4.705 25.248 5.173 26.328 ;
     RECT  5.101 18.432 5.209 18.552 ;
     RECT  4.457 3.36 5.221 3.384 ;
     RECT  5.173 25.2 5.317 26.328 ;
     RECT  4.669 11.76 5.389 11.784 ;
     RECT  5.209 18.432 5.389 18.6 ;
     RECT  4.705 20.448 5.429 23.928 ;
     RECT  5.389 17.856 5.605 18.6 ;
     RECT  5.317 25.152 5.612 26.328 ;
     RECT  5.612 25.104 5.677 26.328 ;
     RECT  5.132 5.232 5.753 8.28 ;
     RECT  5.753 7.296 5.785 8.28 ;
     RECT  5.389 11.76 5.941 12.552 ;
     RECT  4.169 13.92 5.941 14.664 ;
     RECT  5.753 5.232 6.073 6.072 ;
     RECT  4.993 15.984 6.077 16.296 ;
     RECT  5.677 25.008 6.217 26.328 ;
     RECT  5.965 2.544 6.229 2.568 ;
     RECT  6.073 3.984 6.229 4.008 ;
     RECT  6.229 2.544 6.275 4.008 ;
     RECT  5.941 11.76 6.289 14.664 ;
     RECT  6.217 25.008 6.581 26.568 ;
     RECT  6.077 15.984 6.613 16.152 ;
     RECT  5.785 7.296 6.668 8.712 ;
     RECT  6.668 7.296 6.685 8.904 ;
     RECT  6.581 25.536 6.709 26.568 ;
     RECT  5.429 20.736 6.829 23.928 ;
     RECT  5.605 17.472 6.86 18.6 ;
     RECT  6.829 19.776 6.86 23.928 ;
     RECT  6.613 15.84 7.081 16.152 ;
     RECT  6.073 5.184 7.261 6.072 ;
     RECT  6.86 17.472 7.261 23.928 ;
     RECT  6.275 2.88 7.405 3.912 ;
     RECT  7.261 4.992 7.405 6.072 ;
     RECT  6.685 7.296 7.405 9.144 ;
     RECT  6.709 10.368 7.405 10.392 ;
     RECT  7.261 17.472 7.657 24.552 ;
     RECT  6.709 25.536 7.657 27.336 ;
     RECT  6.289 11.472 7.693 14.664 ;
     RECT  7.081 15.84 7.693 16.296 ;
     RECT  7.405 2.88 7.808 6.072 ;
     RECT  7.405 7.296 7.808 10.392 ;
     RECT  7.693 11.472 7.808 16.296 ;
     RECT  7.657 17.472 7.808 27.336 ;
     RECT  7.808 2.148 7.912 27.336 ;
     RECT  7.912 2.418 8.104 27.336 ;
     RECT  8.104 26.976 8.201 27.336 ;
     RECT  8.104 5.328 8.237 6.312 ;
     RECT  8.104 19.536 8.273 21.72 ;
     RECT  8.104 7.344 8.309 10.488 ;
     RECT  8.273 19.536 8.345 21.672 ;
     RECT  8.309 7.344 8.453 9.048 ;
     RECT  8.104 3.312 8.597 4.296 ;
     RECT  8.104 13.104 8.597 18.456 ;
     RECT  8.104 23.136 8.597 25.32 ;
     RECT  8.597 23.136 8.771 24.36 ;
     RECT  8.345 19.872 8.993 21.672 ;
     RECT  8.201 26.976 9.137 27.288 ;
     RECT  8.104 11.472 9.157 11.976 ;
     RECT  8.597 13.104 9.157 17.784 ;
     RECT  8.237 5.328 9.205 6.12 ;
     RECT  9.137 27.264 9.209 27.288 ;
     RECT  9.205 5.328 9.241 6.168 ;
     RECT  8.453 7.344 9.241 8.568 ;
     RECT  8.993 20.784 9.241 21.672 ;
     RECT  9.157 11.472 9.245 17.784 ;
     RECT  9.241 20.784 9.533 21.768 ;
     RECT  8.597 3.744 9.565 4.296 ;
     RECT  9.533 21.456 9.637 21.768 ;
     RECT  9.245 13.152 9.641 17.784 ;
     RECT  8.771 23.472 9.709 24.36 ;
     RECT  9.637 21.456 9.853 21.96 ;
     RECT  9.421 26.208 9.893 26.232 ;
     RECT  9.241 5.328 9.925 8.568 ;
     RECT  8.309 10.464 10.105 10.488 ;
     RECT  9.245 11.472 10.105 11.976 ;
     RECT  9.925 5.328 10.177 9.144 ;
     RECT  10.105 10.464 10.177 11.976 ;
     RECT  9.709 23.472 10.177 25.128 ;
     RECT  9.565 3.6 10.309 4.296 ;
     RECT  10.177 5.328 10.309 11.976 ;
     RECT  9.641 13.152 10.321 17.736 ;
     RECT  10.309 3.6 10.396 11.976 ;
     RECT  10.396 5.328 10.649 11.976 ;
     RECT  10.649 10.128 10.757 11.976 ;
     RECT  10.396 3.6 10.825 3.96 ;
     RECT  10.177 23.376 10.865 25.128 ;
     RECT  10.321 13.008 10.897 17.736 ;
     RECT  10.865 23.376 10.901 24.36 ;
     RECT  10.897 13.008 10.937 17.88 ;
     RECT  10.825 2.976 10.973 3.96 ;
     RECT  10.789 0.096 11.075 0.12 ;
     RECT  9.853 21.456 11.113 22.248 ;
     RECT  10.649 5.328 11.153 9.144 ;
     RECT  10.937 17.856 11.153 17.88 ;
     RECT  10.901 24.192 11.297 24.36 ;
     RECT  10.069 19.2 11.365 19.224 ;
     RECT  10.757 10.128 11.477 10.488 ;
     RECT  11.153 5.328 11.513 8.616 ;
     RECT  11.477 10.464 11.869 10.488 ;
     RECT  10.757 11.472 11.869 11.976 ;
     RECT  10.937 13.008 11.969 16.536 ;
     RECT  11.969 13.008 12.049 16.584 ;
     RECT  11.113 21.456 12.337 22.488 ;
     RECT  11.297 24.336 12.481 24.36 ;
     RECT  9.349 1.728 12.553 1.752 ;
     RECT  12.337 21.408 12.553 22.488 ;
     RECT  12.337 0.096 12.754 0.12 ;
     RECT  12.754 0.096 12.755 0.168 ;
     RECT  12.049 13.008 12.877 17.4 ;
     RECT  11.365 18.48 12.877 19.224 ;
     RECT  12.877 13.008 13.021 19.224 ;
     RECT  9.589 27.312 13.025 27.336 ;
     RECT  12.481 23.76 13.057 24.36 ;
     RECT  13.021 13.008 13.093 19.368 ;
     RECT  13.057 23.76 13.093 25.08 ;
     RECT  11.989 26.16 13.093 26.184 ;
     RECT  11.869 10.464 13.129 11.976 ;
     RECT  13.093 13.008 13.129 20.088 ;
     RECT  12.553 1.728 13.208 2.52 ;
     RECT  10.973 3.936 13.208 3.96 ;
     RECT  11.513 5.472 13.208 8.616 ;
     RECT  13.129 10.464 13.208 20.088 ;
     RECT  12.553 21.12 13.208 22.488 ;
     RECT  13.093 23.76 13.208 26.184 ;
     RECT  13.208 1.728 13.312 27.012 ;
     RECT  12.755 0.144 13.427 0.168 ;
     RECT  13.312 1.728 13.504 26.742 ;
     RECT  13.504 21.072 13.619 25.752 ;
     RECT  13.619 21.072 13.637 23.592 ;
     RECT  13.504 5.472 13.673 9.048 ;
     RECT  13.504 10.656 13.763 20.088 ;
     RECT  13.637 21.456 13.781 23.592 ;
     RECT  13.763 10.656 13.889 19.848 ;
     RECT  13.781 21.456 13.925 21.528 ;
     RECT  13.925 21.456 13.997 21.48 ;
     RECT  13.619 24.864 14.213 25.752 ;
     RECT  13.504 1.728 14.285 4.104 ;
     RECT  14.213 24.864 14.321 25.656 ;
     RECT  14.285 1.728 14.435 2.28 ;
     RECT  13.673 5.472 14.569 9 ;
     RECT  13.889 10.656 14.677 14.664 ;
     RECT  14.285 3.408 14.785 4.104 ;
     RECT  14.569 5.328 14.821 9 ;
     RECT  14.677 10.032 14.821 14.664 ;
     RECT  13.781 22.704 14.857 23.592 ;
     RECT  14.321 25.008 14.861 25.656 ;
     RECT  14.857 22.56 14.969 23.592 ;
     RECT  14.969 23.568 15.109 23.592 ;
     RECT  14.785 3.408 15.325 4.248 ;
     RECT  15.325 2.736 15.397 4.296 ;
     RECT  14.821 5.328 15.397 14.664 ;
     RECT  15.109 23.568 15.469 23.784 ;
     RECT  15.397 2.736 15.473 14.664 ;
     RECT  15.473 3.264 15.581 14.664 ;
     RECT  14.969 22.56 15.613 22.584 ;
     RECT  14.861 25.104 15.617 25.656 ;
     RECT  15.613 21.648 15.685 22.584 ;
     RECT  15.581 3.264 15.725 4.296 ;
     RECT  15.469 23.568 15.96 23.976 ;
     RECT  15.617 25.104 15.96 25.128 ;
     RECT  15.685 20.832 16.021 22.584 ;
     RECT  15.96 23.568 16.021 25.128 ;
     RECT  16.021 20.832 16.049 25.128 ;
     RECT  16.049 20.832 16.108 24.552 ;
     RECT  15.581 5.328 16.333 14.664 ;
     RECT  13.889 15.648 16.333 19.848 ;
     RECT  16.333 5.328 16.357 19.848 ;
     RECT  16.108 20.832 16.357 22.584 ;
     RECT  16.357 5.328 16.403 22.584 ;
     RECT  16.403 18.048 16.481 22.584 ;
     RECT  16.403 5.328 16.556 16.536 ;
     RECT  16.556 5.28 16.643 16.536 ;
     RECT  16.481 18.96 16.697 22.584 ;
     RECT  15.725 3.408 16.733 4.296 ;
     RECT  16.643 5.376 16.877 16.536 ;
     RECT  16.117 27.312 17.093 27.336 ;
     RECT  16.697 22.224 17.111 22.584 ;
     RECT  16.108 23.568 17.111 24.552 ;
     RECT  14.435 1.728 17.129 1.752 ;
     RECT  16.697 18.96 17.129 21.144 ;
     RECT  16.733 3.408 17.233 4.008 ;
     RECT  16.877 5.52 17.273 16.536 ;
     RECT  17.111 22.224 17.345 24.552 ;
     RECT  17.273 5.52 17.381 9.144 ;
     RECT  17.273 10.224 17.413 16.536 ;
     RECT  17.413 10.224 17.453 16.584 ;
     RECT  17.345 22.224 17.453 22.248 ;
     RECT  17.453 10.224 17.525 14.904 ;
     RECT  17.233 3.12 17.593 4.008 ;
     RECT  17.525 10.272 17.603 14.904 ;
     RECT  17.593 3.024 17.629 4.008 ;
     RECT  17.453 15.936 17.641 16.584 ;
     RECT  17.629 2.64 17.953 4.008 ;
     RECT  17.129 20.64 17.953 21.144 ;
     RECT  17.129 18.96 18.181 19.224 ;
     RECT  18.181 18.96 18.421 19.56 ;
     RECT  17.953 2.64 18.565 4.152 ;
     RECT  17.333 27.888 18.565 27.912 ;
     RECT  17.381 5.52 18.601 5.88 ;
     RECT  18.565 1.728 18.608 4.152 ;
     RECT  18.601 5.232 18.608 5.88 ;
     RECT  17.381 7.2 18.608 9.144 ;
     RECT  17.603 10.656 18.608 14.904 ;
     RECT  17.641 15.984 18.608 16.584 ;
     RECT  18.421 18.528 18.608 19.56 ;
     RECT  17.953 20.64 18.608 21.768 ;
     RECT  17.345 23.568 18.608 24.552 ;
     RECT  18.241 25.776 18.608 25.8 ;
     RECT  18.565 27.36 18.608 27.912 ;
     RECT  18.608 1.728 18.712 27.912 ;
     RECT  18.712 1.728 18.904 26.808 ;
     RECT  18.904 15.84 19.181 17.064 ;
     RECT  18.904 18.48 19.289 21.768 ;
     RECT  18.712 27.888 19.321 27.912 ;
     RECT  18.904 2.832 19.325 9 ;
     RECT  19.321 27.888 19.523 27.96 ;
     RECT  18.904 26.784 19.613 26.808 ;
     RECT  19.181 15.84 19.829 17.016 ;
     RECT  19.325 2.832 19.865 4.92 ;
     RECT  19.829 15.84 19.865 16.92 ;
     RECT  18.904 10.656 19.937 14.52 ;
     RECT  19.868 27.312 19.955 27.384 ;
     RECT  18.904 23.568 20.185 25.8 ;
     RECT  19.289 18.528 20.225 21.768 ;
     RECT  19.325 6.144 20.291 9 ;
     RECT  20.225 20.64 20.365 21.768 ;
     RECT  18.904 1.728 20.405 1.752 ;
     RECT  20.185 23.376 20.437 25.8 ;
     RECT  20.291 7.2 20.509 9 ;
     RECT  20.225 18.528 20.653 19.224 ;
     RECT  20.509 7.2 20.657 9.096 ;
     RECT  20.437 23.376 20.773 26.328 ;
     RECT  19.955 27.312 20.773 27.336 ;
     RECT  19.865 3.984 20.917 4.92 ;
     RECT  20.291 6.144 20.917 6.168 ;
     RECT  20.917 3.984 20.963 6.168 ;
     RECT  19.865 2.832 20.977 2.856 ;
     RECT  20.963 3.984 20.977 5.64 ;
     RECT  19.865 15.984 20.977 16.92 ;
     RECT  20.365 20.64 20.977 22.248 ;
     RECT  20.773 23.376 20.977 27.336 ;
     RECT  20.977 2.832 21.004 5.64 ;
     RECT  20.977 15.936 21.013 16.92 ;
     RECT  20.653 18.096 21.013 19.224 ;
     RECT  19.937 10.656 21.121 14.28 ;
     RECT  20.657 7.2 21.265 9 ;
     RECT  21.004 2.832 21.341 5.256 ;
     RECT  21.013 15.936 21.373 19.224 ;
     RECT  20.977 20.64 21.373 27.336 ;
     RECT  21.265 6.96 21.485 9 ;
     RECT  21.485 6.96 21.593 8.808 ;
     RECT  21.593 6.96 21.973 8.52 ;
     RECT  21.973 6.816 22.169 8.52 ;
     RECT  21.121 10.656 22.205 14.952 ;
     RECT  22.169 6.816 22.237 8.328 ;
     RECT  21.341 2.832 22.349 2.856 ;
     RECT  22.205 13.92 22.453 14.952 ;
     RECT  21.373 15.936 22.453 27.336 ;
     RECT  22.205 10.656 22.489 12.888 ;
     RECT  22.453 13.92 22.54 27.336 ;
     RECT  22.489 10.416 22.741 12.888 ;
     RECT  22.237 6.288 22.777 8.328 ;
     RECT  21.341 4.512 22.813 5.256 ;
     RECT  22.777 6.24 22.813 8.328 ;
     RECT  22.54 15.984 22.817 27.336 ;
     RECT  22.741 9.792 22.979 12.888 ;
     RECT  22.813 4.512 23.132 8.328 ;
     RECT  23.132 4.512 23.281 8.712 ;
     RECT  22.979 9.792 23.281 10.44 ;
     RECT  22.979 11.472 23.317 12.888 ;
     RECT  22.54 13.92 23.317 14.712 ;
     RECT  23.281 4.512 24.008 10.44 ;
     RECT  23.317 11.472 24.008 14.712 ;
     RECT  22.817 15.984 24.008 26.616 ;
     RECT  24.008 2.148 24.112 27.012 ;
     RECT  24.112 2.418 24.304 26.742 ;
     RECT  24.304 15.552 24.437 26.568 ;
     RECT  24.437 26.544 24.473 26.568 ;
     RECT  24.437 15.552 24.509 25.32 ;
     RECT  24.509 15.552 24.545 25.224 ;
     RECT  24.545 15.552 24.581 23.928 ;
     RECT  24.545 24.96 24.581 25.128 ;
     RECT  24.581 22.464 24.653 22.488 ;
     RECT  24.581 25.008 24.653 25.032 ;
     RECT  24.304 4.656 24.689 8.04 ;
     RECT  24.304 13.056 24.803 14.184 ;
     RECT  24.803 13.056 24.844 13.32 ;
     RECT  24.304 2.832 24.899 3.528 ;
     RECT  24.689 4.656 25.013 7.944 ;
     RECT  24.581 23.904 25.085 23.928 ;
     RECT  24.581 15.552 25.333 21.288 ;
     RECT  24.304 10.368 25.373 10.392 ;
     RECT  25.333 15.408 25.445 21.288 ;
     RECT  24.844 13.296 25.553 13.32 ;
     RECT  24.304 11.472 25.589 11.976 ;
     RECT  25.445 21.264 25.589 21.288 ;
     RECT  25.445 15.408 25.697 19.32 ;
     RECT  25.697 15.408 25.769 17.688 ;
     RECT  25.697 19.248 25.805 19.32 ;
     RECT  25.013 5.328 25.841 7.944 ;
     RECT  25.841 7.248 25.861 7.944 ;
     RECT  25.513 9.12 25.861 9.144 ;
     RECT  25.841 5.328 25.877 6.264 ;
     RECT  25.861 7.248 25.877 9.144 ;
     RECT  25.769 15.408 25.877 17.16 ;
     RECT  25.805 19.296 25.877 19.32 ;
     RECT  25.877 7.92 25.907 9.144 ;
     RECT  25.907 7.92 25.913 8.664 ;
     RECT  25.913 8.496 25.948 8.664 ;
     RECT  25.877 6.24 25.949 6.264 ;
     RECT  25.877 15.552 26.201 16.296 ;
     RECT  25.589 11.952 26.809 11.976 ;
     RECT  26.773 19.776 27.313 19.8 ;
     RECT  26.773 21.168 27.313 21.192 ;
     RECT  26.773 3.504 27.349 4.44 ;
     RECT  25.948 8.64 27.349 8.664 ;
     RECT  26.809 10.944 27.349 12.168 ;
     RECT  26.809 13.68 27.349 14.28 ;
     RECT  26.201 16.08 27.349 16.296 ;
     RECT  27.313 18.192 27.349 18.216 ;
     RECT  27.313 19.776 27.349 21.192 ;
     RECT  26.773 23.568 27.349 25.896 ;
     RECT  27.349 23.328 27.889 26.136 ;
     RECT  27.349 19.776 28.465 22.104 ;
     RECT  27.925 2.304 28.501 2.328 ;
     RECT  27.349 3.504 28.501 9.576 ;
     RECT  28.465 19.536 28.501 22.104 ;
     RECT  27.889 23.328 28.501 26.376 ;
     RECT  26.773 27.36 28.501 27.384 ;
     RECT  28.501 2.304 29.076 2.328 ;
     RECT  28.501 2.328 29.1 2.592 ;
     RECT  28.501 2.592 29.076 2.616 ;
     RECT  28.501 2.616 29.1 2.928 ;
     RECT  28.501 2.928 29.076 2.952 ;
     RECT  28.501 2.952 29.1 3.216 ;
     RECT  28.501 3.216 29.076 3.24 ;
     RECT  28.501 3.24 29.1 3.504 ;
     RECT  28.501 3.504 29.076 3.528 ;
     RECT  28.501 3.528 29.1 3.792 ;
     RECT  28.501 3.792 29.076 3.816 ;
     RECT  28.501 3.816 29.1 4.128 ;
     RECT  28.501 4.128 29.076 4.152 ;
     RECT  28.501 4.152 29.1 4.416 ;
     RECT  28.501 4.416 29.076 4.44 ;
     RECT  28.501 4.44 29.1 4.704 ;
     RECT  28.501 4.704 29.076 4.728 ;
     RECT  28.501 4.728 29.1 5.04 ;
     RECT  28.501 5.04 29.076 5.064 ;
     RECT  28.501 5.064 29.1 5.328 ;
     RECT  28.501 5.328 29.076 5.352 ;
     RECT  28.501 5.352 29.1 5.616 ;
     RECT  28.501 5.616 29.076 5.64 ;
     RECT  28.501 5.64 29.1 5.952 ;
     RECT  28.501 5.952 29.076 5.976 ;
     RECT  28.501 5.976 29.1 6.24 ;
     RECT  28.501 6.24 29.076 6.264 ;
     RECT  28.501 6.264 29.1 6.528 ;
     RECT  28.501 6.528 29.076 6.552 ;
     RECT  28.501 6.552 29.1 6.816 ;
     RECT  28.501 6.816 29.076 6.84 ;
     RECT  28.501 6.84 29.1 7.152 ;
     RECT  28.501 7.152 29.076 7.176 ;
     RECT  28.501 7.176 29.1 7.44 ;
     RECT  28.501 7.44 29.076 7.464 ;
     RECT  28.501 7.464 29.1 7.728 ;
     RECT  28.501 7.728 29.076 7.752 ;
     RECT  28.501 7.752 29.1 8.064 ;
     RECT  28.501 8.064 29.076 8.088 ;
     RECT  28.501 8.088 29.1 8.352 ;
     RECT  28.501 8.352 29.076 8.376 ;
     RECT  28.501 8.376 29.1 8.64 ;
     RECT  28.501 8.64 29.076 8.664 ;
     RECT  28.501 8.664 29.1 8.976 ;
     RECT  28.501 8.976 29.076 9 ;
     RECT  28.501 9 29.1 9.264 ;
     RECT  28.501 9.264 29.076 9.288 ;
     RECT  28.501 9.288 29.1 9.552 ;
     RECT  28.501 9.552 29.076 9.576 ;
     RECT  27.349 10.944 29.076 10.968 ;
     RECT  27.349 10.968 29.1 11.232 ;
     RECT  27.349 11.232 29.076 11.256 ;
     RECT  27.349 11.256 29.1 11.568 ;
     RECT  27.349 11.568 29.076 11.592 ;
     RECT  27.349 11.592 29.1 11.856 ;
     RECT  27.349 11.856 29.076 11.88 ;
     RECT  27.349 11.88 29.1 12.144 ;
     RECT  27.349 12.144 29.076 12.168 ;
     RECT  27.349 12.168 29.1 12.432 ;
     RECT  27.349 12.432 29.076 12.456 ;
     RECT  27.349 12.456 29.1 12.768 ;
     RECT  27.349 12.768 29.076 12.792 ;
     RECT  27.349 12.792 29.1 13.056 ;
     RECT  27.349 13.056 29.076 13.08 ;
     RECT  27.349 13.08 29.1 13.344 ;
     RECT  27.349 13.344 29.076 13.368 ;
     RECT  27.349 13.368 29.1 13.68 ;
     RECT  27.349 13.68 29.076 13.704 ;
     RECT  27.349 13.704 29.1 13.968 ;
     RECT  27.349 13.968 29.076 13.992 ;
     RECT  27.349 13.992 29.1 14.256 ;
     RECT  27.349 14.256 29.076 14.28 ;
     RECT  27.349 14.28 29.1 14.592 ;
     RECT  27.349 14.592 29.076 14.616 ;
     RECT  27.349 14.616 29.1 14.88 ;
     RECT  27.349 14.88 29.076 14.904 ;
     RECT  27.349 14.904 29.1 15.168 ;
     RECT  27.349 15.168 29.076 15.192 ;
     RECT  27.349 15.192 29.1 15.456 ;
     RECT  27.349 15.456 29.076 15.48 ;
     RECT  27.349 15.48 29.1 15.792 ;
     RECT  27.349 15.792 29.076 15.816 ;
     RECT  27.349 15.816 29.1 16.08 ;
     RECT  27.349 16.08 29.076 16.104 ;
     RECT  27.349 16.104 29.1 16.368 ;
     RECT  27.349 16.368 29.076 16.392 ;
     RECT  27.349 16.392 29.1 16.704 ;
     RECT  27.349 16.704 29.076 16.728 ;
     RECT  27.349 16.728 29.1 16.992 ;
     RECT  27.349 16.992 29.076 17.016 ;
     RECT  27.349 17.016 29.1 17.28 ;
     RECT  27.349 17.28 29.076 17.304 ;
     RECT  27.349 17.304 29.1 17.616 ;
     RECT  27.349 17.616 29.076 17.64 ;
     RECT  27.349 17.64 29.1 17.904 ;
     RECT  27.349 17.904 29.076 17.928 ;
     RECT  27.349 17.928 29.1 18.192 ;
     RECT  27.349 18.192 29.076 18.216 ;
     RECT  28.501 19.536 29.076 19.56 ;
     RECT  28.501 19.56 29.1 19.776 ;
     RECT  28.501 19.776 29.076 19.8 ;
     RECT  28.501 19.8 29.1 20.016 ;
     RECT  28.501 20.016 29.076 20.04 ;
     RECT  28.501 20.04 29.1 20.256 ;
     RECT  28.501 20.256 29.076 20.28 ;
     RECT  28.501 20.28 29.1 20.448 ;
     RECT  28.501 20.448 29.076 20.472 ;
     RECT  28.501 20.472 29.1 20.688 ;
     RECT  28.501 20.688 29.076 20.712 ;
     RECT  28.501 20.712 29.1 20.928 ;
     RECT  28.501 20.928 29.076 20.952 ;
     RECT  28.501 20.952 29.1 21.168 ;
     RECT  28.501 21.168 29.076 21.192 ;
     RECT  28.501 21.192 29.1 21.408 ;
     RECT  28.501 21.408 29.076 21.432 ;
     RECT  28.501 21.432 29.1 21.648 ;
     RECT  28.501 21.648 29.076 21.672 ;
     RECT  28.501 21.672 29.1 21.84 ;
     RECT  28.501 21.84 29.076 21.864 ;
     RECT  28.501 21.864 29.1 22.08 ;
     RECT  28.501 22.08 29.076 22.104 ;
     RECT  28.501 22.104 29.1 22.32 ;
     RECT  28.501 22.32 29.076 22.344 ;
     RECT  28.501 22.344 29.1 22.56 ;
     RECT  28.501 22.56 29.076 22.584 ;
     RECT  28.501 22.584 29.1 23.328 ;
     RECT  28.501 23.328 29.076 23.352 ;
     RECT  28.501 23.352 29.1 23.568 ;
     RECT  28.501 23.568 29.076 23.592 ;
     RECT  28.501 23.592 29.1 23.808 ;
     RECT  28.501 23.808 29.076 23.832 ;
     RECT  28.501 23.832 29.1 24 ;
     RECT  28.501 24 29.076 24.024 ;
     RECT  28.501 24.024 29.1 24.24 ;
     RECT  28.501 24.24 29.076 24.264 ;
     RECT  28.501 24.264 29.1 24.48 ;
     RECT  28.501 24.48 29.076 24.504 ;
     RECT  28.501 24.504 29.1 24.72 ;
     RECT  28.501 24.72 29.076 24.744 ;
     RECT  28.501 24.744 29.1 24.96 ;
     RECT  28.501 24.96 29.076 24.984 ;
     RECT  28.501 24.984 29.1 25.152 ;
     RECT  28.501 25.152 29.076 25.176 ;
     RECT  28.501 25.176 29.1 25.392 ;
     RECT  28.501 25.392 29.076 25.416 ;
     RECT  28.501 25.416 29.1 25.632 ;
     RECT  28.501 25.632 29.076 25.656 ;
     RECT  28.501 25.656 29.1 25.872 ;
     RECT  28.501 25.872 29.076 25.896 ;
     RECT  28.501 25.896 29.1 26.112 ;
     RECT  28.501 26.112 29.076 26.136 ;
     RECT  28.501 26.136 29.1 26.352 ;
     RECT  28.501 26.352 29.076 26.376 ;
     RECT  28.501 26.376 29.1 27.024 ;
     RECT  28.501 27.024 29.076 27.048 ;
     RECT  28.501 27.048 29.1 27.36 ;
     RECT  28.501 27.36 29.076 27.384 ;
    LAYER M5 ;
     RECT  9.384 0.016 9.696 0.084 ;
     RECT  9.72 0.016 10.032 0.084 ;
     RECT  10.056 0.016 10.368 0.084 ;
     RECT  10.392 0.016 10.704 0.084 ;
     RECT  10.728 0.016 11.04 0.084 ;
     RECT  11.064 0.016 11.376 0.084 ;
     RECT  11.4 0.016 11.712 0.084 ;
     RECT  11.736 0.016 12.048 0.084 ;
     RECT  12.072 0.016 12.384 0.084 ;
     RECT  12.408 0.016 12.72 0.084 ;
     RECT  12.744 0.016 13.056 0.084 ;
     RECT  13.08 0.016 13.392 0.084 ;
     RECT  13.416 0.016 13.728 0.084 ;
     RECT  13.752 0.016 14.064 0.084 ;
     RECT  14.088 0.016 14.4 0.084 ;
     RECT  14.424 0.016 14.736 0.084 ;
     RECT  14.76 0.016 15.072 0.084 ;
     RECT  15.096 0.016 15.408 0.084 ;
     RECT  15.432 0.016 15.744 0.084 ;
     RECT  15.768 0.016 16.08 0.084 ;
     RECT  16.104 0.016 16.416 0.084 ;
     RECT  16.44 0.016 16.752 0.084 ;
     RECT  16.776 0.016 17.088 0.084 ;
     RECT  17.112 0.016 18 0.084 ;
     RECT  18.024 0.016 18.672 0.084 ;
     RECT  18.696 0.016 19.344 0.084 ;
     RECT  9.36 0.084 19.368 1.763 ;
     RECT  2.4 2.137 2.52 2.151 ;
     RECT  7.8 2.137 7.92 2.151 ;
     RECT  24 2.137 24.12 2.151 ;
     RECT  13.2 1.763 14.424 2.291 ;
     RECT  24 2.151 24.312 2.821 ;
     RECT  7.8 2.151 8.112 3.397 ;
     RECT  6.24 2.533 6.264 4.019 ;
     RECT  24 2.821 24.888 4.501 ;
     RECT  5.184 3.349 5.208 5.267 ;
     RECT  16.608 5.269 16.632 5.461 ;
     RECT  23.184 4.501 24.888 5.747 ;
     RECT  7.8 3.397 8.376 5.843 ;
     RECT  20.928 5.221 20.952 6.133 ;
     RECT  20.256 6.133 20.952 6.179 ;
     RECT  15.744 5.461 16.632 6.181 ;
     RECT  18 1.763 18.912 6.181 ;
     RECT  2.4 2.151 2.712 6.229 ;
     RECT  15.744 6.181 18.912 6.229 ;
     RECT  15.36 6.229 18.912 6.275 ;
     RECT  10.32 4.117 10.344 6.899 ;
     RECT  21.984 6.805 22.008 7.043 ;
     RECT  15.36 6.275 15.768 7.475 ;
     RECT  20.256 6.179 20.28 7.475 ;
     RECT  23.184 5.747 24.312 7.717 ;
     RECT  2.4 6.229 3.432 8.195 ;
     RECT  11.04 7.909 11.064 8.579 ;
     RECT  15.744 7.475 15.768 8.581 ;
     RECT  6.288 7.957 6.312 8.677 ;
     RECT  7.8 5.843 8.112 8.677 ;
     RECT  6.288 8.677 8.112 8.723 ;
     RECT  17.136 6.275 18.912 9.013 ;
     RECT  25.872 8.485 25.896 9.155 ;
     RECT  17.088 9.013 18.912 9.205 ;
     RECT  16.992 9.205 18.912 9.251 ;
     RECT  14.832 8.581 15.768 9.779 ;
     RECT  16.992 9.251 17.016 10.067 ;
     RECT  6.72 8.723 8.112 10.163 ;
     RECT  18 9.251 18.912 10.261 ;
     RECT  15.744 9.779 15.768 10.307 ;
     RECT  6.72 10.163 6.744 10.403 ;
     RECT  13.2 2.291 13.512 10.693 ;
     RECT  14.688 10.021 14.712 10.693 ;
     RECT  2.4 8.195 2.712 11.365 ;
     RECT  2.4 11.365 2.904 12.083 ;
     RECT  6.72 11.941 6.744 12.755 ;
     RECT  22.56 7.717 24.312 13.045 ;
     RECT  9.168 12.325 9.192 13.139 ;
     RECT  13.2 10.693 14.712 13.283 ;
     RECT  22.56 13.045 24.792 13.331 ;
     RECT  17.568 10.261 18.912 14.147 ;
     RECT  24 13.331 24.792 14.195 ;
     RECT  5.952 13.045 5.976 14.627 ;
     RECT  3.936 13.957 3.96 14.675 ;
     RECT  13.2 13.283 13.656 14.723 ;
     RECT  22.56 13.331 22.584 14.773 ;
     RECT  22.464 14.773 22.584 15.491 ;
     RECT  13.2 14.723 13.608 15.877 ;
     RECT  17.568 14.147 17.592 15.971 ;
     RECT  7.8 10.163 8.112 15.973 ;
     RECT  13.104 15.877 13.608 15.973 ;
     RECT  14.688 13.283 14.712 15.973 ;
     RECT  24 14.195 24.312 16.021 ;
     RECT  6.768 15.829 6.792 16.163 ;
     RECT  23.904 16.021 24.312 16.163 ;
     RECT  18.6 14.147 18.912 16.165 ;
     RECT  22.56 15.491 22.584 16.165 ;
     RECT  13.104 15.973 14.712 16.261 ;
     RECT  18.192 16.165 18.912 16.261 ;
     RECT  13.104 16.261 14.856 16.307 ;
     RECT  14.688 16.307 14.856 16.451 ;
     RECT  12 14.197 12.024 16.595 ;
     RECT  18.192 16.261 19.032 16.741 ;
     RECT  18.192 16.741 19.272 16.883 ;
     RECT  7.8 15.973 8.712 17.077 ;
     RECT  22.56 16.165 22.776 17.123 ;
     RECT  7.8 17.077 8.76 17.461 ;
     RECT  22.56 17.123 22.632 17.605 ;
     RECT  12.096 17.365 12.12 17.701 ;
     RECT  13.104 16.307 13.608 17.701 ;
     RECT  10.464 16.741 10.488 17.747 ;
     RECT  12.096 17.701 13.608 17.941 ;
     RECT  12.096 17.941 13.704 18.083 ;
     RECT  22.176 17.605 22.632 18.085 ;
     RECT  21.648 18.085 22.632 18.275 ;
     RECT  21.744 18.275 22.632 18.419 ;
     RECT  24 16.163 24.312 19.045 ;
     RECT  12.096 18.083 12.12 19.235 ;
     RECT  13.104 18.083 13.704 19.285 ;
     RECT  14.688 16.451 14.712 19.285 ;
     RECT  24 19.045 24.504 19.285 ;
     RECT  2.4 12.083 2.712 19.333 ;
     RECT  13.104 19.285 14.712 19.427 ;
     RECT  18.192 16.883 18.912 19.571 ;
     RECT  22.56 18.419 22.632 19.763 ;
     RECT  24 19.285 24.84 19.955 ;
     RECT  6.912 17.461 8.76 20.099 ;
     RECT  13.104 19.427 13.752 20.099 ;
     RECT  16.368 17.365 16.392 21.637 ;
     RECT  16.032 21.637 16.392 21.683 ;
     RECT  13.104 20.099 13.704 22.115 ;
     RECT  2.4 19.333 3.288 22.307 ;
     RECT  7.8 20.099 8.76 22.741 ;
     RECT  22.608 19.763 22.632 22.981 ;
     RECT  24 19.955 24.504 22.981 ;
     RECT  22.608 22.981 24.504 23.603 ;
     RECT  22.608 23.603 24.456 23.699 ;
     RECT  22.608 23.699 24.312 23.795 ;
     RECT  22.608 23.795 22.632 23.987 ;
     RECT  7.68 22.741 8.76 24.083 ;
     RECT  13.104 22.115 13.608 24.227 ;
     RECT  7.8 24.083 8.76 24.371 ;
     RECT  16.032 21.683 16.056 24.467 ;
     RECT  22.032 24.949 22.056 25.141 ;
     RECT  22.032 25.141 22.344 25.285 ;
     RECT  24 23.795 24.312 25.285 ;
     RECT  22.032 25.285 24.312 25.379 ;
     RECT  13.104 24.227 13.512 25.715 ;
     RECT  20.448 23.941 20.472 25.715 ;
     RECT  5.664 25.093 5.688 25.811 ;
     RECT  23.04 25.379 24.312 26.243 ;
     RECT  20.784 26.773 20.808 26.821 ;
     RECT  22.032 25.379 22.056 26.821 ;
     RECT  7.8 24.371 8.112 26.965 ;
     RECT  2.4 22.307 2.712 27.009 ;
     RECT  13.2 25.715 13.512 27.009 ;
     RECT  24 26.243 24.312 27.009 ;
     RECT  2.4 27.009 2.52 27.023 ;
     RECT  13.2 27.009 13.32 27.023 ;
     RECT  24 27.009 24.12 27.023 ;
     RECT  7.8 26.965 8.664 27.253 ;
     RECT  7.8 27.253 9.144 27.301 ;
     RECT  12 26.149 12.024 27.301 ;
     RECT  20.784 26.821 22.056 27.301 ;
     RECT  20.352 27.301 22.488 27.349 ;
     RECT  16.128 27.301 17.016 27.877 ;
     RECT  18.6 19.571 18.912 27.877 ;
     RECT  19.92 27.349 22.488 27.877 ;
     RECT  6.72 27.301 12.984 29.076 ;
     RECT  6.744 29.076 7.2 29.136 ;
     RECT  7.224 29.076 7.68 29.136 ;
     RECT  7.704 29.076 8.16 29.136 ;
     RECT  8.184 29.076 8.64 29.136 ;
     RECT  8.664 29.076 9.12 29.136 ;
     RECT  9.144 29.076 9.6 29.136 ;
     RECT  9.624 29.076 10.08 29.136 ;
     RECT  10.104 29.076 10.56 29.136 ;
     RECT  10.584 29.076 11.04 29.136 ;
     RECT  11.064 29.076 11.52 29.136 ;
     RECT  11.544 29.076 12 29.136 ;
     RECT  12.024 29.076 12.48 29.136 ;
     RECT  12.504 29.076 12.96 29.136 ;
     RECT  16.128 27.877 22.488 29.076 ;
     RECT  16.152 29.076 16.56 29.136 ;
     RECT  16.584 29.076 16.992 29.136 ;
     RECT  17.016 29.076 17.376 29.136 ;
     RECT  17.4 29.076 17.808 29.136 ;
     RECT  17.832 29.076 18.24 29.136 ;
     RECT  18.264 29.076 18.672 29.136 ;
     RECT  18.696 29.076 19.104 29.136 ;
     RECT  19.128 29.076 19.488 29.136 ;
     RECT  19.512 29.076 19.92 29.136 ;
     RECT  19.944 29.076 20.352 29.136 ;
     RECT  20.376 29.076 20.784 29.136 ;
     RECT  20.808 29.076 21.168 29.136 ;
     RECT  21.192 29.076 21.6 29.136 ;
     RECT  21.624 29.076 22.032 29.136 ;
     RECT  22.056 29.076 22.464 29.136 ;
     RECT  5.208 3.349 6.24 4.019 ;
     RECT  16.632 5.269 18 6.181 ;
     RECT  18.912 6.133 20.256 7.475 ;
     RECT  15.768 6.275 17.136 9.013 ;
     RECT  22.008 6.805 23.184 7.043 ;
     RECT  22.56 7.043 23.184 7.717 ;
     RECT  15.36 7.475 15.744 8.581 ;
     RECT  6.312 7.957 7.8 8.677 ;
     RECT  13.512 8.581 14.832 9.779 ;
     RECT  15.768 9.013 17.088 9.205 ;
     RECT  15.768 9.205 16.992 10.067 ;
     RECT  17.016 9.251 18 10.067 ;
     RECT  13.512 9.779 15.744 10.021 ;
     RECT  13.512 10.021 14.688 10.693 ;
     RECT  14.712 10.021 15.744 10.307 ;
     RECT  17.568 10.067 18 10.261 ;
     RECT  6.744 10.163 7.8 10.403 ;
     RECT  6.744 11.941 7.8 12.755 ;
     RECT  8.112 12.325 9.168 13.139 ;
     RECT  13.656 13.283 14.688 14.723 ;
     RECT  22.584 13.331 24 16.021 ;
     RECT  2.712 13.957 3.936 14.675 ;
     RECT  17.592 14.147 18.6 15.971 ;
     RECT  12.024 14.197 13.2 15.877 ;
     RECT  13.608 14.723 14.688 15.973 ;
     RECT  6.792 15.829 7.8 16.163 ;
     RECT  12.024 15.877 13.104 16.595 ;
     RECT  18.192 15.971 18.6 16.165 ;
     RECT  22.584 16.021 23.904 16.163 ;
     RECT  6.912 16.163 7.8 17.461 ;
     RECT  22.584 16.163 24 16.165 ;
     RECT  22.776 16.165 24 17.123 ;
     RECT  13.608 16.307 14.688 17.941 ;
     RECT  12.096 16.595 13.104 17.365 ;
     RECT  22.632 17.123 24 22.981 ;
     RECT  12.12 17.365 13.104 17.701 ;
     RECT  13.704 17.941 14.688 19.285 ;
     RECT  12.12 18.083 13.104 19.235 ;
     RECT  22.632 23.795 24 23.987 ;
     RECT  22.608 23.987 24 24.949 ;
     RECT  22.056 24.949 24 25.141 ;
     RECT  22.344 25.141 24 25.285 ;
     RECT  22.056 25.379 23.04 26.243 ;
     RECT  13.104 25.715 13.2 26.149 ;
     RECT  12.024 26.149 13.2 27.023 ;
     RECT  22.056 26.243 24 27.023 ;
     RECT  20.808 26.773 22.032 26.821 ;
     RECT  12.024 27.023 12.984 27.301 ;
     RECT  22.056 27.023 22.488 27.301 ;
     RECT  18.912 27.301 20.352 27.349 ;
     RECT  18.912 27.349 19.92 27.877 ;
  END
END ot_hidx_s3_ctl
END LIBRARY
